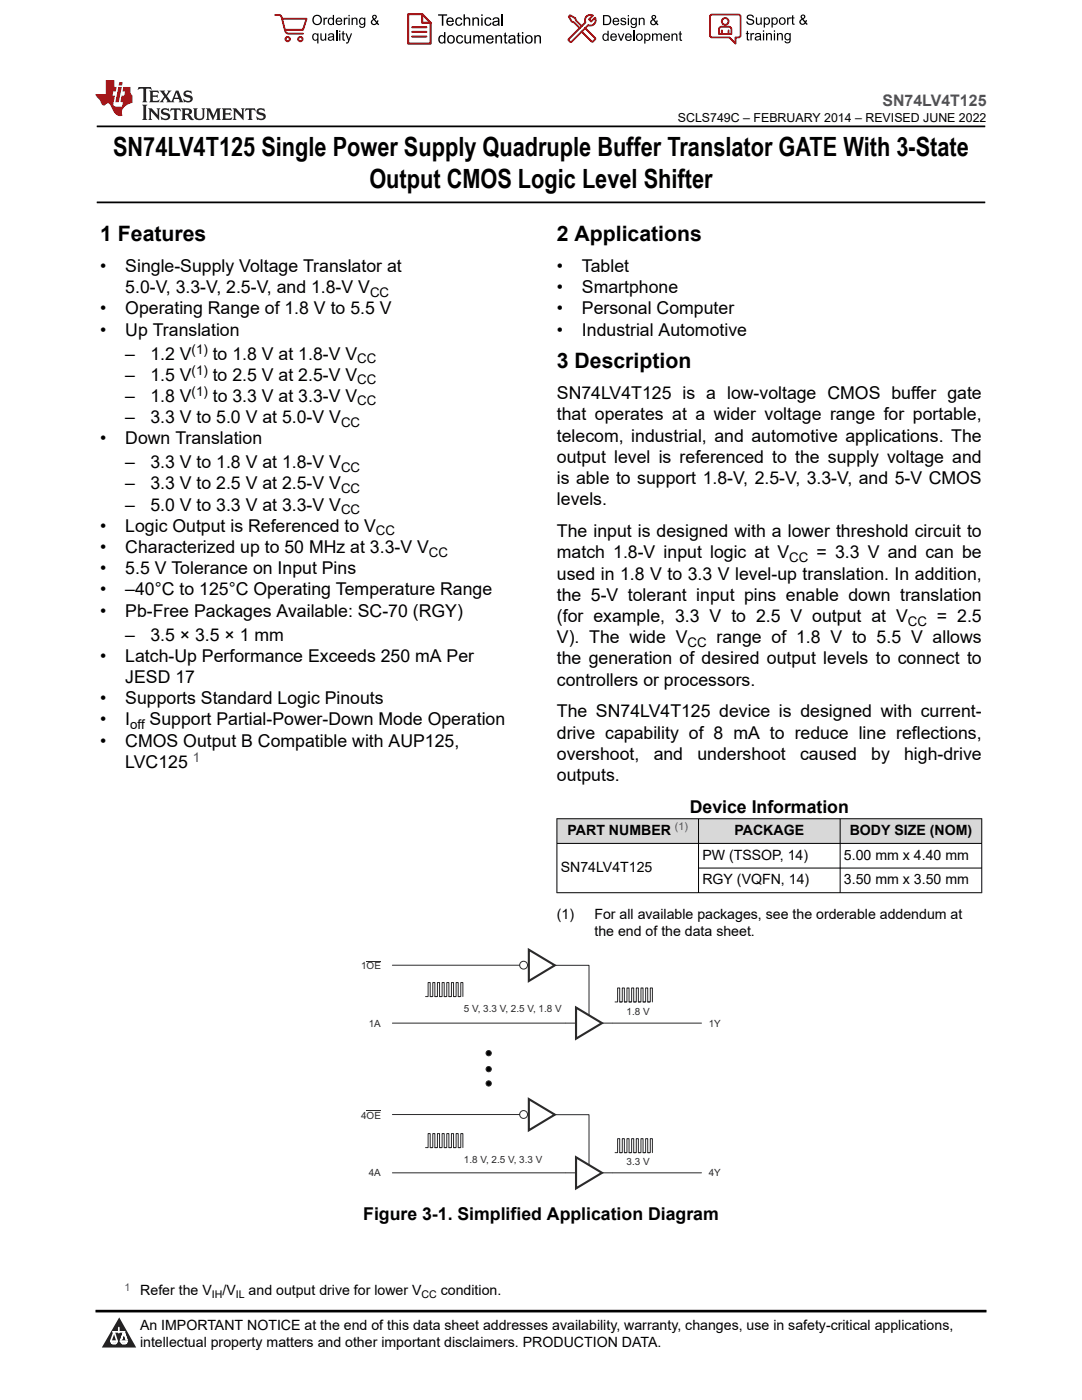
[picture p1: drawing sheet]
<svg xmlns="http://www.w3.org/2000/svg" width="216mm" height="279mm" viewBox="0 0 216 279" stroke-linecap="round" stroke-linejoin="round" font-family="sans-serif">
<defs><g id="words">
<g font-size="5.3">
<text x="22.6" y="31.2">SN74LV4T125 Single Power Supply Quadruple Buffer Translator GATE With 3-State</text>
<text x="73.7" y="37.5">Output CMOS Logic Level Shifter</text>
</g>
<g font-size="4.2">
<text x="20" y="48.1">1 Features</text>
<text x="111.1" y="48.1">2 Applications</text>
<text x="111.1" y="73.5">3 Description</text>
</g>
<g font-size="3.5">
<text x="20" y="54.3">•</text>
<text x="25" y="54.3">Single-Supply Voltage Translator at</text>
<text x="25" y="58.5">5.0-V, 3.3-V, 2.5-V, and 1.8-V V</text>
<text x="111.1" y="54.3">•</text>
<text x="111.1" y="58.5">•</text>
<text x="116.1" y="54.3">Tablet</text>
<text x="116.1" y="58.5">Smartphone</text>
<text x="20" y="62.8">•</text>
<text x="25" y="62.8">Operating Range of 1.8 V to 5.5 V</text>
<text x="111.1" y="62.8">•</text>
<text x="116.1" y="62.8">Personal Computer</text>
<text x="20" y="67">•</text>
<text x="25" y="67">Up Translation</text>
<text x="25" y="71.7">–</text>
<text x="30" y="71.7">1.2 V</text>
<text x="42.5" y="71.7">to 1.8 V at 1.8-V V</text>
<text x="111.1" y="67">•</text>
<text x="116.1" y="67">Industrial Automotive</text>
<text x="25" y="76">–</text>
<text x="30" y="76">1.5 V</text>
<text x="42.5" y="76">to 2.5 V at 2.5-V V</text>
<text x="25" y="80.2">–</text>
<text x="30" y="80.2">1.8 V</text>
<text x="42.5" y="80.2">to 3.3 V at 3.3-V V</text>
<text x="111.1" y="79.7">SN74LV4T125 is a low-voltage CMOS buffer gate</text>
<text x="111.1" y="83.9">that operates at a wider voltage range for portable,</text>
<text x="20" y="88.7">•</text>
<text x="25" y="88.7">Down Translation</text>
<text x="25" y="84.4">–</text>
<text x="30" y="84.4">3.3 V to 5.0 V at 5.0-V V</text>
<text x="111.1" y="88.2">telecom, industrial, and automotive applications. The</text>
<text x="25" y="93.4">–</text>
<text x="30" y="93.4">3.3 V to 1.8 V at 1.8-V V</text>
<text x="111.1" y="92.4">output level is referenced to the supply voltage and</text>
<text x="25" y="97.7">–</text>
<text x="25" y="101.9">–</text>
<text x="30" y="101.9">5.0 V to 3.3 V at 3.3-V V</text>
<text x="30" y="97.7">3.3 V to 2.5 V at 2.5-V V</text>
<text x="111.1" y="96.6">is able to support 1.8-V, 2.5-V, 3.3-V, and 5-V CMOS</text>
<text x="111.1" y="100.9">levels.</text>
<text x="20" y="106.1">•</text>
<text x="25" y="106.1">Logic Output is Referenced to V</text>
<text x="111.1" y="107.2">The input is designed with a lower threshold circuit to</text>
<text x="20" y="110.4">•</text>
<text x="25" y="110.4">Characterized up to 50 MHz at 3.3-V V</text>
<text x="111.1" y="111.4">match 1.8-V input logic at V</text>
<text x="162.9" y="111.4">= 3.3 V and can be</text>
<text x="20" y="114.6">•</text>
<text x="20" y="118.8">•</text>
<text x="25" y="114.6">5.5 V Tolerance on Input Pins</text>
<text x="25" y="118.8">–40°C to 125°C Operating Temperature Range</text>
<text x="111.1" y="115.7">used in 1.8 V to 3.3 V level-up translation. In addition,</text>
<text x="111.1" y="119.9">the 5-V tolerant input pins enable down translation</text>
<text x="20" y="123.1">•</text>
<text x="25" y="123.1">Pb-Free Packages Available: SC-70 (RGY)</text>
<text x="111.1" y="124.1">(for example, 3.3 V to 2.5 V output at V</text>
<text x="187" y="124.1">= 2.5</text>
<text x="25" y="127.8">–</text>
<text x="30" y="127.8">3.5 × 3.5 × 1 mm</text>
<text x="111.1" y="128.4">V). The wide V</text>
<text x="143" y="128.4">range of 1.8 V to 5.5 V allows</text>
<text x="20" y="132.1">•</text>
<text x="25" y="132.1">Latch-Up Performance Exceeds 250 mA Per</text>
<text x="25" y="136.3">JESD 17</text>
<text x="111.1" y="136.8">controllers or processors.</text>
<text x="111.1" y="132.6">the generation of desired output levels to connect to</text>
<text x="20" y="140.5">•</text>
<text x="25" y="140.5">Supports Standard Logic Pinouts</text>
<text x="111.1" y="143.2">The SN74LV4T125 device is designed with current-</text>
<text x="20" y="149">•</text>
<text x="20" y="144.8">•</text>
<text x="25" y="144.8">I</text>
<text x="25" y="149">CMOS Output B Compatible with AUP125,</text>
<text x="29.9" y="144.8">Support Partial-Power-Down Mode Operation</text>
<text x="111.1" y="147.4">drive capability of 8 mA to reduce line reflections,</text>
<text x="25" y="153.2">LVC125</text>
<text x="111.1" y="151.7">overshoot,</text>
<text x="111.1" y="155.9">outputs.</text>
<text x="130.4" y="151.7">and</text>
<text x="139.2" y="151.7">undershoot</text>
<text x="159.6" y="151.7">caused</text>
<text x="173.8" y="151.7">by</text>
<text x="180.4" y="151.7">high-drive</text>
<text x="137.6" y="162.2">Device Information</text>
<text x="72.5" y="243.5">Figure 3-1. Simplified Application Diagram</text>
</g>
<text font-size="3.2" fill="#00f" x="176.1" y="21.1">SN74LV4T125</text>
<g font-size="2.8">
<text x="113.2" y="166.7">PART NUMBER</text>
<text x="146.6" y="166.7">PACKAGE</text>
<text x="169.5" y="166.7">BODY SIZE (NOM)</text>
<text x="140.2" y="171.6">PW (TSSOP, 14)</text>
<text x="168.4" y="171.6">5.00 mm x 4.40 mm</text>
<text x="111.9" y="174.1">SN74LV4T125</text>
<text x="140.2" y="176.5">RGY (VQFN, 14)</text>
<text x="168.4" y="176.5">3.50 mm x 3.50 mm</text>
<text x="111.1" y="183.3">(1)</text>
<text x="118.6" y="183.3">For all available packages, see the orderable addendum at</text>
<text x="118.6" y="186.7">the end of the data sheet.</text>
<text x="28" y="258.5">Refer the V</text>
<text x="44.4" y="258.5">/V</text>
<text x="49.6" y="258.5">and output drive for lower V</text>
<text x="88" y="258.5">condition.</text>
<text x="27.9" y="265.5">An IMPORTANT NOTICE at the end of this data sheet addresses availability, warranty, changes, use in safety-critical applications,</text>
<text x="27.9" y="268.9">intellectual property matters and other important disclaimers. PRODUCTION DATA.</text>
</g>
<g font-size="2.6">
<text x="73.8" y="59.2">CC</text>
<text x="38.2" y="70.6">(1)</text>
<text x="38.2" y="74.8">(1)</text>
<text x="71.3" y="76.7">CC</text>
<text x="71.3" y="72.5">CC</text>
<text x="38.2" y="79">(1)</text>
<text x="71.3" y="80.9">CC</text>
<text x="68" y="85.2">CC</text>
<text x="68" y="94.1">CC</text>
<text x="68" y="98.4">CC</text>
<text x="68" y="102.6">CC</text>
<text x="75" y="106.8">CC</text>
<text x="85.6" y="111.1">CC</text>
<text x="157.5" y="112.1">CC</text>
<text x="181.1" y="124.8">CC</text>
<text x="137.2" y="129.1">CC</text>
<text x="26" y="145.5">off</text>
</g>
<text font-size="2.6" fill="#00f" x="38.5" y="152.1">1</text>
<text font-size="2.5" x="135.3" y="24.3">SCLS749C – FEBRUARY 2014 – REVISED JUNE 2022</text>
<g font-size="2.1" fill="#00f">
<text x="134.7" y="165.7">(1)</text>
<text x="24.8" y="257.6">1</text>
</g>
<g font-size="2.1">
<text x="42.3" y="259.1">IH</text>
<text x="47.1" y="259.1">IL</text>
<text x="84.1" y="259.1">CC</text>
</g>
<g font-size="2" fill="#2b292a">
<text x="72.1" y="193.5">1OE</text>
<text x="92.5" y="202">5 V, 3.3 V, 2.5 V, 1.8 V</text>
<text x="125" y="202.5">1.8 V</text>
<text x="73.6" y="204.9">1A</text>
<text x="141.4" y="204.9">1Y</text>
<text x="72.1" y="223.3">4OE</text>
<text x="92.6" y="232.2">1.8 V, 2.5 V, 3.3 V</text>
<text x="125" y="232.6">3.3 V</text>
<text x="73.6" y="234.8">4A</text>
<text x="141.4" y="234.8">4Y</text>
</g>
</g></defs>
<path d="M19.3 25.2h177.3M19.3 40.4h177.3" fill="none" stroke="#000" stroke-width=".35"/>
<g fill="#d8d8d8">
<path d="M111.1 163.4h84.8v4.9h-84.8z" fill-rule="evenodd"/>
<path d="M111.2 163.5h28.1v4.8h-28.1z" fill-rule="evenodd"/>
<path d="M139.4 163.5h28.2v4.8h-28.2z" fill-rule="evenodd"/>
<path d="M167.7 163.5h28.1v4.8h-28.1z" fill-rule="evenodd"/>
</g>
<path d="M111.1 163.4h84.9M111.1 168.3h84.9M111.1 178.2h84.9M111.1 163.3v14.9M139.4 163.3v14.9M139.4 173.2h56.6M167.6 163.3v14.9M195.9 163.3v14.9" fill="none" stroke="#000" stroke-width=".2"/>
<g fill="none" stroke="#2b292a" stroke-width=".2">
<path d="M73.2 191.8h2.8M78.3 192.6h25.4M84.9 198.9h.5v-2.8h.4v2.8h.4M85.8 198.9h.6v-2.8h.4v2.8h.4M86.8 198.9h.5v-2.8h.4v2.8h.4M87.7 198.9h.5v-2.8h.4v2.8h.4M88.6 198.9h.5v-2.8h.5v2.8h.4M89.6 198.9h.5v-2.8h.4v2.8h.4M90.5 198.9h.5v-2.8h.4v2.8h.4M91.4 198.9h.5v-2.8h.5v2.8M110.7 192.6h6.8v10M122.7 200h.5v-2.8h.5v2.8h.4"/>
<path d="M123.7 200h.5v-2.8h.4v2.8h.4M124.6 200h.5v-2.8h.4v2.8h.4M125.5 200h.5v-2.8h.5v2.8h.3M126.5 200h.5v-2.8h.4v2.8h.4M127.4 200h.5v-2.8h.4v2.8h.4M128.3 200h.5v-2.8h.4v2.8h.4M129.2 200h.6v-2.8h.4v2.8M78.3 204.2h36.6M120.1 204.2h19.9M73.2 221.6h2.8M78.3 234.1h36.6M78.3 222.4h25.4"/>
<path d="M84.9 229h.5v-2.8h.4v2.8h.4M85.8 229h.6v-2.8h.4v2.8h.4M86.8 229h.5v-2.8h.4v2.8h.4M87.7 229h.5v-2.8h.4v2.8h.4M88.6 229h.5v-2.8h.5v2.8h.4M89.6 229h.5v-2.8h.4v2.8h.4M90.5 229h.5v-2.8h.4v2.8h.4M91.4 229h.5v-2.8h.5v2.8M110.7 222.5h6.8v9.9M120.1 234.1h19.9M122.7 230h.5v-2.8h.5v2.8h.4M123.7 230h.5v-2.8h.4v2.8h.4"/>
<path d="M124.6 230h.5v-2.8h.4v2.8h.4M125.5 230h.5v-2.8h.5v2.8h.3M126.5 230h.5v-2.8h.4v2.8h.4M127.4 230h.5v-2.8h.4v2.8h.4M128.3 230h.5v-2.8h.4v2.8h.4M129.2 230h.6v-2.8h.4v2.8"/>
<circle cx="104.5" cy="192.6" r=".78"/>
<circle cx="97.5" cy="213.4" r=".53"/>
<circle cx="97.5" cy="216.2" r=".53"/>
<circle cx="97.5" cy="210.2" r=".53"/>
<circle cx="104.5" cy="222.4" r=".78"/>
</g>
<path d="M105.5 189.5l5.2 3.1-5.2 3.2zM105.5 219.3l5.2 3.1-5.2 3.2zM114.9 201.1l5.2 3.1-5.2 3.1zM114.9 231l5.2 3.1-5.2 3.1z" fill="none" stroke="#2b292a" stroke-width=".42"/>
<g fill="#000">
<circle cx="97.5" cy="213.4" r=".53"/>
<circle cx="97.5" cy="216.2" r=".53"/>
<circle cx="97.5" cy="210.2" r=".53"/>
</g>
<path d="M0 0h215.9v23.8h-215.9z" fill-rule="evenodd" fill="#fff"/>
<path d="M27.7 17.4l-.2 .6 .5-.3h.6v.1v2.2l-.2 .4h1l-.2-.4v-2.2v-.1h.5l.5 .3-.1-.6zM29.8 18.1l.2 .4v1.5l-.2 .4h1.9l.1-.6a1.08 1.08 0 0 1-1.3 .2v-.7h.6l.4 .2v-.6l-.4 .2h-.6v-.6l.2-.1a1 1 0 0 1 1 .2l-.1-.5zM31.8 18.1l1 1.1-1 1.2h.9l-.2-.2 .4-.7 .5 .7-.2 .2h1.6l-.2-.2 .1-.4h1l.1 .4-.1 .2h.9l-.2-.3-.8-2h-.5l-1 2.2-.8-1.1 .9-1.1h-.8l.2 .2-.5 .7-.3-.7 .1-.2zM35.2 18.5l.4 1h-.8zM36.8 18.2a.65 .65 0 0 0-.2 .7 .65 .65 0 0 0 .6 .5l.7 .2 .1 .2a.79 .79 0 0 1-.7 .4 .79 .79 0 0 1-.7-.5l.1 .7 .2-.1a.93 .93 0 0 0 1.1 .1 .93 .93 0 0 0 .4-1 1.46 1.46 0 0 0-1.2-.6l-.1-.3a1.09 1.09 0 0 1 1.2 .2l-.2-.6-.1 .1-.6-.2zM28.4 20.9l.2 .4v2.3l-.2 .3h1l-.2-.3v-2.3l.2-.4zM29.6 21.6l.2 .4v1.6l-.2 .3h.8l-.3-.3v-1.4l1.7 1.8v-2l.2-.4h-.8l.2 .2 .1 1.1-1.2-1.3zM32.3 21.8a.65 .65 0 0 0-.2 .7 .65 .65 0 0 0 .7 .4l.6 .2 .1 .2a.79 .79 0 0 1-.7 .4 .79 .79 0 0 1-.7-.5l.1 .7 .2-.1a.93 .93 0 0 0 1.1 .1 .93 .93 0 0 0 .4-.9 1.46 1.46 0 0 0-1.2-.6l-.1-.4a1.09 1.09 0 0 1 1.2 .2l-.2-.6-.1 .1-.6-.1zM34.1 21.6l-.1 .7a.63 .63 0 0 1 .7-.4l.1 1.7-.3 .3h1l-.2-.3v-1.7a.66 .66 0 0 1 .8 .4l-.1-.7zM36.2 21.6l.2 .4v1.6l-.2 .3h.9l-.2-.2v-.7h.5l.1 .2a.79 .79 0 0 0 1.2 .6l-1-.9a.61 .61 0 0 0 .6-.6 .61 .61 0 0 0-.5-.6zM36.9 21.9h.2a.47 .47 0 0 1 .5 .1 .47 .47 0 0 1 .1 .5l-.2 .2h-.6zM38.5 21.6l.2 .2a2.27 2.27 0 0 0 .4 2 1.04 1.04 0 0 0 1.7-.7v-1.3l.2-.2h-.8l.2 .4v1.1a.6 .6 0 0 1-.6 .6 .6 .6 0 0 1-.6-.6v-1.1l.3-.4zM41.1 21.6l.2 .4v1.6l-.2 .3h.7l-.2-.3v-1.5l.9 1.9 .8-1.9v1.5l-.2 .3h1l-.3-.3v-1.6l.3-.4h-.8l-.7 1.5-.7-1.5zM44.3 21.6l.2 .4v1.6l-.2 .3h1.9l.1-.5a1.09 1.09 0 0 1-1.3 .1v-.6h.6l.4 .1v-.6l-.4 .2h-.6v-.6l.2-.1a1.01 1.01 0 0 1 1 .3l-.1-.6zM46.4 21.6l.3 .4v1.6l-.3 .3h.8l-.2-.3v-1.4l1.6 1.8v-2l.2-.4h-.7l.2 .2v1.1l-1.2-1.3zM49 21.6l-.1 .7a.63 .63 0 0 1 .8-.4v1.7l-.3 .3h1l-.2-.3v-1.7a.66 .66 0 0 1 .8 .4l-.1-.7zM51.4 21.8a.65 .65 0 0 0-.2 .7 .65 .65 0 0 0 .6 .4l.6 .2 .2 .2a.79 .79 0 0 1-.8 .4 .79 .79 0 0 1-.6-.5l.1 .7 .2-.1a.93 .93 0 0 0 1 .1 .93 .93 0 0 0 .5-.9 1.46 1.46 0 0 0-1.3-.6l-.1-.4a1.09 1.09 0 0 1 1.3 .2l-.2-.6-.2 .1-.5-.1z" fill="#231f20"/>
<path d="M21.1 16v2.8h-2.1l.1 .3 .9 1a.95 .95 0 0 0 .9 .9 .59 .59 0 0 1 .6-.4 .59 .59 0 0 1 .5 .4l.4 .8a1.59 1.59 0 0 0 2.1 1.3 1.61 1.61 0 0 1 1-2.2l1-.4-.1-1.5a1.59 1.59 0 0 1-.4-1.6h-1.4l-.2 .9h.5l-.1 .8h-.5l-.2 1v.2l.4 .1-.2 .9h-.6a.73 .73 0 0 1-1.1-.7l.3-1.5h-.5l.2-.8h.5l.2-.9h-.5v-1.4zM23.6 17.4l-.6 3h.7l.6-3zM23.8 16.4l-.1 .7h.7l.1-.7z" fill="#ed1c24"/>
<g fill="#000">
<path d="M62.3 4a1 1 0 0 1 2 0 1 1 0 0 1-2 0zM62.8 3.4a.78 .78 0 0 0-.1 1.1 .78 .78 0 0 0 1.1 .1 .78 .78 0 0 0 .1-1.1 .78 .78 0 0 0-1.1-.1z" fill-rule="evenodd"/>
<path d="M62.5 6.8l.4-.2 .4 .3v-.2h.2v2h-.2v-.7a.68 .68 0 0 1-.9-.1 .68 .68 0 0 1 0-.9zM62.6 7a.51 .51 0 0 0-.1 .6 .51 .51 0 0 0 .7 .2 .51 .51 0 0 0 .1-.7 .51 .51 0 0 0-.7-.1z" fill-rule="evenodd"/>
<path d="M64.5 3.5h.3v.3l.1-.3h.3l.1 .1-.1 .2a.32 .32 0 0 0-.3 0 .32 .32 0 0 0-.1 .4v.8h-.3z" fill-rule="evenodd"/>
<path d="M63.9 6.7h.3v.8a.36 .36 0 0 0 .3 .4 .36 .36 0 0 0 .4-.5v-.7h.2v1.4h-.2v-.2a.51 .51 0 0 1-.6 .2 .51 .51 0 0 1-.4-.5z" fill-rule="evenodd"/>
<path d="M65.6 3.7l.4-.2 .4 .2v-.7h.3v2h-.3v-.2a.7 .7 0 0 1-1-.1 .7 .7 0 0 1 .2-1zM65.8 3.8a.51 .51 0 0 0-.1 .7 .51 .51 0 0 0 .6 .2 .51 .51 0 0 0 .1-.7 .51 .51 0 0 0-.6-.2z" fill-rule="evenodd"/>
<path d="M65.6 6.8a.66 .66 0 0 1 .8-.1 .66 .66 0 0 1 .3 .8v.6h-.2l-.1-.2a.52 .52 0 0 1-.7 .2 .52 .52 0 0 1-.2-.6l.3-.2a.42 .42 0 0 0 .6-.3l-.3-.2-.3 .1-.1 .2h-.3zM65.7 7.6a.35 .35 0 0 0 .3 .4 .35 .35 0 0 0 .4-.4v-.2z" fill-rule="evenodd"/>
<path d="M67.7 6.1h.2v.3h-.2zM67.7 6.7h.2v1.4h-.2z" fill-rule="evenodd"/>
<path d="M67.1 3.7a.68 .68 0 0 1 .9-.1 .68 .68 0 0 1 .3 .7h-1.1a.42 .42 0 0 0 .3 .5 .42 .42 0 0 0 .5-.3h.3a.73 .73 0 0 1-1.1 .4 .73 .73 0 0 1-.1-1.2zM67.4 3.8l-.2 .3h.8l-.2-.4z" fill-rule="evenodd"/>
<path d="M68.6 3.5h.2v.3l.2-.3h.3l.1 .1-.1 .2a.32 .32 0 0 0-.4 0 .32 .32 0 0 0-.1 .4v.8h-.2z" fill-rule="evenodd"/>
<path d="M68.3 6.3l.3-.1v.5h.2v.1h-.2v.9l.3 .4a.36 .36 0 0 1-.4 0 .36 .36 0 0 1-.2-.4v-.9h-.1v-.1h.1z" fill-rule="evenodd"/>
<path d="M68.9 6.7h.3l.4 1.1 .4-1.1h.3l-.6 1.4a.51 .51 0 0 1-.6 .6l-.1-.3h.3l.2-.3z" fill-rule="evenodd"/>
<path d="M69.5 3h.3v.3h-.3zM69.5 3.5h.3v1.5h-.3z" fill-rule="evenodd"/>
<path d="M70.2 3.5h.2v.2a.52 .52 0 0 1 .6-.2 .52 .52 0 0 1 .3 .6v.9h-.2v-.9a.34 .34 0 0 0-.3-.4 .34 .34 0 0 0-.4 .3v1h-.2z" fill-rule="evenodd"/>
<path d="M71.8 3.7l.4-.2 .5 .2v-.2h.2v1.3a.64 .64 0 0 1-.5 .8 .64 .64 0 0 1-.7-.5h.2a.41 .41 0 0 0 .5 .2 .41 .41 0 0 0 .2-.5 .69 .69 0 0 1-.9-.1 .69 .69 0 0 1 .1-1zM72 3.8a.5 .5 0 0 0-.1 .7 .5 .5 0 0 0 .7 .1 .5 .5 0 0 0 .1-.6 .5 .5 0 0 0-.7-.2z" fill-rule="evenodd"/>
<path d="M74.4 3.1a.47 .47 0 0 1 .7 .1 .47 .47 0 0 1-.3 .7l.4 .4 .1-.3 .2 .1-.1 .4 .3 .3-.2 .2-.3-.3a.63 .63 0 0 1-1 .1 .63 .63 0 0 1 .3-1l-.3-.4zM74.5 3.4a.27 .27 0 0 0 .5 0 .27 .27 0 0 0-.5 0zM74.4 4.1a.4 .4 0 0 0 0 .6 .4 .4 0 0 0 .6-.1l-.4-.6z" fill-rule="evenodd"/>
<path d="M87.4 2.9h1.8v.2h-.7v2h-.3v-2h-.8z" fill-rule="evenodd"/>
<path d="M87.6 7.2l.5-.2 .5 .2v-.8h.3v2.3h-.3v-.2a.76 .76 0 0 1-1-.1 .76 .76 0 0 1-.1-1zM87.9 7.4a.58 .58 0 0 0-.2 .7 .58 .58 0 0 0 .8 .2 .58 .58 0 0 0 .1-.7 .58 .58 0 0 0-.7-.2z" fill-rule="evenodd"/>
<path d="M89.5 7.2a.81 .81 0 0 1 1.1 .1 .81 .81 0 0 1-.2 1.2 .81 .81 0 0 1-1.1-.2l-.1-.7zM89.6 7.4a.57 .57 0 0 0 0 .8 .57 .57 0 0 0 .8 0 .57 .57 0 0 0 0-.7 .57 .57 0 0 0-.8-.1z" fill-rule="evenodd"/>
<path d="M89.3 3.7a.77 .77 0 0 1 .9-.2 .77 .77 0 0 1 .4 .9h-1.3a.48 .48 0 0 0 .4 .5 .48 .48 0 0 0 .6-.3h.3a.83 .83 0 0 1-1.3 .4 .83 .83 0 0 1 0-1.3zM89.5 3.8l-.2 .4h1l-.3-.5z" fill-rule="evenodd"/>
<path d="M91 3.7a.7 .7 0 0 1 1.2 .3h-.2a.45 .45 0 0 0-.6-.3 .45 .45 0 0 0-.3 .6 .45 .45 0 0 0 .3 .6 .45 .45 0 0 0 .6-.4l.3 .1a.76 .76 0 0 1-1.1 .5 .76 .76 0 0 1-.3-1.1z" fill-rule="evenodd"/>
<path d="M91.2 7.2a.7 .7 0 0 1 1.2 .3l-.3 .1a.45 .45 0 0 0-.5-.4 .45 .45 0 0 0-.3 .7 .45 .45 0 0 0 .3 .6 .45 .45 0 0 0 .6-.4h.2a.76 .76 0 0 1-1 .5 .76 .76 0 0 1-.4-1.1z" fill-rule="evenodd"/>
<path d="M92.5 2.9h.3v.8a.59 .59 0 0 1 .7-.2 .59 .59 0 0 1 .3 .6v1h-.2v-1a.4 .4 0 0 0-.5-.4 .4 .4 0 0 0-.3 .5v.9h-.3z" fill-rule="evenodd"/>
<path d="M92.7 7h.2v.9a.41 .41 0 0 0 .5 .6 .41 .41 0 0 0 .3-.6v-.9h.3v1.7h-.3v-.3a.58 .58 0 0 1-.7 .3 .58 .58 0 0 1-.3-.7z" fill-rule="evenodd"/>
<path d="M94.3 3.5h.2v.2a.59 .59 0 0 1 .7-.2 .59 .59 0 0 1 .4 .6v1h-.3v-1a.41 .41 0 0 0-.4-.4 .41 .41 0 0 0-.4 .5v.9h-.2z" fill-rule="evenodd"/>
<path d="M94.4 7h.3v.3a.56 .56 0 0 1 1 0 .54 .54 0 0 1 .6-.3 .54 .54 0 0 1 .4 .5v1.2h-.3v-1.1a.34 .34 0 0 0-.3-.4 .34 .34 0 0 0-.4 .3v1.2h-.3v-1.1a.38 .38 0 0 0-.5-.3 .38 .38 0 0 0-.2 .5v.9h-.3z" fill-rule="evenodd"/>
<path d="M96 2.9h.3v.3h-.3zM96 3.5h.3v1.6h-.3z" fill-rule="evenodd"/>
<path d="M96.8 3.7a.7 .7 0 0 1 1.3 .3h-.3a.45 .45 0 0 0-.6-.3 .45 .45 0 0 0-.3 .6 .45 .45 0 0 0 .3 .6 .45 .45 0 0 0 .6-.4l.3 .1a.76 .76 0 0 1-1.1 .5 .76 .76 0 0 1-.3-1.1z" fill-rule="evenodd"/>
<path d="M97.2 7.2a.77 .77 0 0 1 .9-.1 .77 .77 0 0 1 .4 .8h-1.2a.48 .48 0 0 0 .3 .6 .48 .48 0 0 0 .6-.4l.3 .1a.83 .83 0 0 1-1.3 .3 .83 .83 0 0 1 0-1.3zM97.4 7.4l-.1 .3h.9l-.2-.4z" fill-rule="evenodd"/>
<path d="M98.8 7h.3v.3a.59 .59 0 0 1 .7-.3 .59 .59 0 0 1 .4 .7v1h-.3v-1a.41 .41 0 0 0-.5-.5 .41 .41 0 0 0-.3 .6v.9h-.3z" fill-rule="evenodd"/>
<path d="M98.4 3.7a.74 .74 0 0 1 1-.2 .74 .74 0 0 1 .3 .9v.7h-.3v-.2a.59 .59 0 0 1-.8 .3 .59 .59 0 0 1-.3-.8l1.1-.3a.42 .42 0 0 0-.4-.4 .42 .42 0 0 0-.5 .3h-.2zM98.6 4.5a.36 .36 0 0 0 .2 .5 .36 .36 0 0 0 .5-.2l.1-.5z" fill-rule="evenodd"/>
<path d="M100.7 6.6l.2-.1v.5h.3v.2h-.3v1l.1 .2h.2l.1 .3a.41 .41 0 0 1-.5-.1 .41 .41 0 0 1-.1-.4v-1h-.2v-.2h.2z" fill-rule="evenodd"/>
<path d="M101.6 7.2a.74 .74 0 0 1 .9-.2 .74 .74 0 0 1 .3 1l.1 .7h-.3v-.2a.59 .59 0 0 1-.8 .2 .59 .59 0 0 1-.3-.8l1-.3a.42 .42 0 0 0-.3-.4 .42 .42 0 0 0-.5 .3h-.3zM101.8 8.1a.36 .36 0 0 0 .1 .5 .36 .36 0 0 0 .5-.3l.2-.4z" fill-rule="evenodd"/>
<path d="M103.3 6.6l.3-.1v.5h.3v.2h-.3v1l.1 .2h.2v.3a.41 .41 0 0 1-.5-.1 .41 .41 0 0 1-.1-.4v-1h-.2v-.2h.2z" fill-rule="evenodd"/>
<path d="M104.1 6.4h.3v.3h-.3zM104.1 7h.3v1.7h-.3z" fill-rule="evenodd"/>
<path d="M105 7.2a.81 .81 0 0 1 1.1 .1 .81 .81 0 0 1-.1 1.2 .81 .81 0 0 1-1.2-.2v-.7zM105.2 7.4a.57 .57 0 0 0-.1 .8 .57 .57 0 0 0 .8 0 .57 .57 0 0 0 0-.7 .57 .57 0 0 0-.7-.1z" fill-rule="evenodd"/>
<path d="M106.6 7h.3v.3a.59 .59 0 0 1 .7-.3 .59 .59 0 0 1 .4 .7v1h-.3v-1a.41 .41 0 0 0-.5-.5 .41 .41 0 0 0-.3 .6v.9h-.3z" fill-rule="evenodd"/>
<path d="M120.3 3h.7a1 1 0 0 1 1 1 1 1 0 0 1-1 1h-.7zM120.6 3.2v1.6h.4a.77 .77 0 0 0 .7-.8 .77 .77 0 0 0-.7-.8z" fill-rule="evenodd"/>
<path d="M120.4 6.9l.4-.2 .4 .2v-.8h.3v2h-.3v-.1a.7 .7 0 0 1-.9-.2 .7 .7 0 0 1 .1-.9zM120.6 7a.51 .51 0 0 0-.1 .7 .51 .51 0 0 0 .6 .1 .51 .51 0 0 0 .1-.6 .51 .51 0 0 0-.6-.2z" fill-rule="evenodd"/>
<path d="M122 6.9a.68 .68 0 0 1 .8-.2 .68 .68 0 0 1 .3 .8h-1.1a.42 .42 0 0 0 .3 .5 .42 .42 0 0 0 .5-.3h.3a.73 .73 0 0 1-1.1 .3 .73 .73 0 0 1 0-1.1zM122.2 7l-.2 .3h.8l-.2-.4z" fill-rule="evenodd"/>
<path d="M122.4 3.7a.68 .68 0 0 1 .8-.1 .68 .68 0 0 1 .4 .8h-1.1a.42 .42 0 0 0 .3 .4 .42 .42 0 0 0 .5-.3l.3 .1a.73 .73 0 0 1-1.2 .3 .73 .73 0 0 1 0-1.2zM122.6 3.8l-.1 .3h.8l-.2-.3z" fill-rule="evenodd"/>
<path d="M123.9 3.7l.1-.1a.62 .62 0 0 1 .9 .3l-.2 .1a.29 .29 0 0 0-.3-.3 .29 .29 0 0 0-.3 .3l.1 .1a.58 .58 0 0 1 .6 .1 .58 .58 0 0 1 .1 .6 .67 .67 0 0 1-1.1-.2l.2-.1a.33 .33 0 0 0 .4 .4 .33 .33 0 0 0 .3-.4 .71 .71 0 0 1-.9-.6z" fill-rule="evenodd"/>
<path d="M123.3 6.7h.2l.4 1.2 .4-1.2h.3l-.6 1.4h-.2z" fill-rule="evenodd"/>
<path d="M125.3 3h.2v.3h-.2zM125.3 3.6h.2v1.4h-.2z" fill-rule="evenodd"/>
<path d="M124.9 6.9a.68 .68 0 0 1 .8-.2 .68 .68 0 0 1 .4 .8h-1.1a.42 .42 0 0 0 .3 .5 .42 .42 0 0 0 .5-.3h.3a.73 .73 0 0 1-1.2 .3 .73 .73 0 0 1 0-1.1zM125.1 7l-.1 .3h.8l-.2-.4z" fill-rule="evenodd"/>
<path d="M126 3.7l.4-.2 .4 .2v-.1h.3v1.2a.64 .64 0 0 1-.5 .8 .64 .64 0 0 1-.8-.5l.3 .1a.41 .41 0 0 0 .5 .2 .41 .41 0 0 0 .2-.6 .69 .69 0 0 1-.9-.1 .69 .69 0 0 1 .1-1zM126.2 3.9a.5 .5 0 0 0-.1 .6 .5 .5 0 0 0 .6 .2 .5 .5 0 0 0 .2-.7 .5 .5 0 0 0-.7-.1z" fill-rule="evenodd"/>
<path d="M126.9 7.4a.73 .73 0 0 1 1.4 0 .73 .73 0 0 1-1.4 0zM127.3 7a.5 .5 0 0 0-.1 .7 .5 .5 0 0 0 .7 0 .5 .5 0 0 0 0-.6 .5 .5 0 0 0-.6-.1z" fill-rule="evenodd"/>
<path d="M127.5 3.6h.2v.2a.52 .52 0 0 1 .6-.3 .52 .52 0 0 1 .3 .6v.9h-.2v-.9a.34 .34 0 0 0-.3-.4 .34 .34 0 0 0-.4 .3v1h-.2z" fill-rule="evenodd"/>
<path d="M128.5 6.7h.3v.2a.67 .67 0 0 1 .9 0 .67 .67 0 0 1 0 .9 .55 .55 0 0 1-.9 .2v.7h-.3zM128.9 7a.5 .5 0 0 0-.1 .7 .5 .5 0 0 0 .6 .1 .5 .5 0 0 0 .2-.6 .5 .5 0 0 0-.7-.2z" fill-rule="evenodd"/>
<path d="M130.1 6.7h.2v.2a.49 .49 0 0 1 .9 0l.4-.2a.42 .42 0 0 1 .5 .4v1h-.3v-.9a.3 .3 0 0 0-.2-.3 .3 .3 0 0 0-.4 .2v1h-.2v-.9a.33 .33 0 0 0-.5-.3 .33 .33 0 0 0-.2 .5v.7h-.2z" fill-rule="evenodd"/>
<path d="M130.1 3.1a.47 .47 0 0 1 .8 .1 .47 .47 0 0 1-.3 .7l.3 .4 .1-.2h.3l-.2 .5 .3 .3-.2 .2-.3-.3a.63 .63 0 0 1-1 .1 .63 .63 0 0 1 .3-1l-.2-.5zM130.2 3.5a.27 .27 0 0 0 .5 0 .27 .27 0 0 0-.5 0zM130.2 4.1a.4 .4 0 0 0 0 .7 .4 .4 0 0 0 .6-.2l-.5-.6z" fill-rule="evenodd"/>
<path d="M132.5 6.9a.68 .68 0 0 1 .9-.2 .68 .68 0 0 1 .3 .8h-1.1a.42 .42 0 0 0 .3 .5 .42 .42 0 0 0 .5-.3h.3a.73 .73 0 0 1-1.1 .3 .73 .73 0 0 1-.1-1.1zM132.7 7l-.1 .3h.8l-.2-.4z" fill-rule="evenodd"/>
<path d="M134 6.7h.2v.2a.52 .52 0 0 1 .6-.2 .52 .52 0 0 1 .4 .6v.8h-.3v-.8a.34 .34 0 0 0-.2-.4 .34 .34 0 0 0-.4 .2l-.1 1h-.2z" fill-rule="evenodd"/>
<path d="M135.6 6.3l.2-.1v.5h.3v.2h-.3v.8l.3 .4a.36 .36 0 0 1-.4 0 .36 .36 0 0 1-.1-.4v-.8h-.2v-.2h.2z" fill-rule="evenodd"/>
<path d="M149.2 3a.8 .8 0 0 1 1.2 .5h-.2a.44 .44 0 0 0-.5-.4 .44 .44 0 0 0-.4 .5l.2 .1a.9 .9 0 0 1 1 .8 .84 .84 0 0 1-.9 .5 .84 .84 0 0 1-.7-.7h.3a.52 .52 0 0 0 .5 .5 .52 .52 0 0 0 .5-.6l-.2-.1a.85 .85 0 0 1-1-.8z" fill-rule="evenodd"/>
<path d="M149 6.3l.3-.2v.5h.2v.2h-.2v.9l.2 .4a.36 .36 0 0 1-.4-.1 .36 .36 0 0 1-.1-.4v-.8h-.2v-.2h.2z" fill-rule="evenodd"/>
<path d="M149.7 6.6h.3v.2l.1-.2h.3l.1 .1-.1 .2a.32 .32 0 0 0-.3 0 .32 .32 0 0 0-.1 .4v.8h-.3z" fill-rule="evenodd"/>
<path d="M150.7 6.8a.66 .66 0 0 1 .9-.2 .66 .66 0 0 1 .3 .9v.6h-.2l-.1-.2a.52 .52 0 0 1-.7 .2 .52 .52 0 0 1-.2-.7l.2-.1a.42 .42 0 0 0 .7-.3l-.3-.2h-.3l-.1 .3-.3-.1zM150.9 7.5a.35 .35 0 0 0 .3 .5 .35 .35 0 0 0 .4-.4v-.3z" fill-rule="evenodd"/>
<path d="M150.8 3.5h.3v.8a.36 .36 0 0 0 .3 .5 .36 .36 0 0 0 .4-.5v-.8h.2v1.4h-.2v-.2a.51 .51 0 0 1-.6 .3 .51 .51 0 0 1-.4-.6z" fill-rule="evenodd"/>
<path d="M152.2 6.1h.3v.2h-.3zM152.2 6.6h.3v1.5h-.3z" fill-rule="evenodd"/>
<path d="M152.4 3.5h.2v.2a.67 .67 0 0 1 .9 0 .67 .67 0 0 1 .1 .9 .55 .55 0 0 1-1 .2v.7h-.2zM152.7 3.8a.5 .5 0 0 0-.1 .7 .5 .5 0 0 0 .7 .1 .5 .5 0 0 0 .1-.6 .5 .5 0 0 0-.7-.2z" fill-rule="evenodd"/>
<path d="M152.9 6.6h.2v.2a.52 .52 0 0 1 .6-.2 .52 .52 0 0 1 .3 .6v.9h-.2v-.9a.34 .34 0 0 0-.3-.4 .34 .34 0 0 0-.4 .2v1.1h-.2z" fill-rule="evenodd"/>
<path d="M153.9 3.5h.3v.2a.67 .67 0 0 1 .9 0 .67 .67 0 0 1 0 .9 .55 .55 0 0 1-.9 .2v.7h-.3zM154.3 3.8a.5 .5 0 0 0-.1 .7 .5 .5 0 0 0 .6 .1 .5 .5 0 0 0 .2-.6 .5 .5 0 0 0-.7-.2z" fill-rule="evenodd"/>
<path d="M154.4 6.1h.3v.2h-.3zM154.4 6.6h.3v1.5h-.3z" fill-rule="evenodd"/>
<path d="M155 6.6h.3v.2a.52 .52 0 0 1 .6-.2 .52 .52 0 0 1 .3 .6v.9h-.2v-.9a.34 .34 0 0 0-.3-.4 .34 .34 0 0 0-.4 .2v1.1h-.3z" fill-rule="evenodd"/>
<path d="M155.4 4.2a.75 .75 0 0 1 1.5 0 .75 .75 0 0 1-1.5 0zM155.8 3.8a.5 .5 0 0 0-.1 .7 .5 .5 0 0 0 .8 0 .5 .5 0 0 0 0-.7 .5 .5 0 0 0-.7 0z" fill-rule="evenodd"/>
<path d="M156.7 6.8l.4-.2 .5 .2v-.2h.2v1.3a.64 .64 0 0 1-.5 .7 .64 .64 0 0 1-.8-.4h.3a.41 .41 0 0 0 .5 .2 .41 .41 0 0 0 .2-.5 .69 .69 0 0 1-.9-.1 .69 .69 0 0 1 .1-1zM156.9 6.9a.5 .5 0 0 0-.1 .7 .5 .5 0 0 0 .6 .1 .5 .5 0 0 0 .2-.7 .5 .5 0 0 0-.7-.1z" fill-rule="evenodd"/>
<path d="M157.1 3.5h.2v.2l.1-.2h.3h.2l-.1 .3a.32 .32 0 0 0-.4 0 .32 .32 0 0 0-.1 .4v.7h-.2z" fill-rule="evenodd"/>
<path d="M158 3.1l.3-.1v.5h.2v.2h-.2v.8l.3 .4a.36 .36 0 0 1-.4 0 .36 .36 0 0 1-.2-.4v-.8h-.1v-.2h.1z" fill-rule="evenodd"/>
<path d="M159.9 3a.47 .47 0 0 1 .7 .1 .47 .47 0 0 1-.3 .7l.4 .5 .1-.3h.2l-.1 .5 .3 .3-.2 .2-.3-.3a.63 .63 0 0 1-1 .1 .63 .63 0 0 1 .3-1l-.3-.5zM160 3.4a.27 .27 0 0 0 .5 0 .27 .27 0 0 0-.5 0zM159.9 4.1a.4 .4 0 0 0 0 .6 .4 .4 0 0 0 .6-.2l-.4-.6z" fill-rule="evenodd"/>
</g>
<path d="M67.2 6.1v2M126.5 6.1v2" fill="none" stroke="#000" stroke-width=".25"/>
<g fill="none" stroke="#de0000" stroke-width=".37">
<path d="M54.9 3h.9a1.19 1.19 0 0 1 .6 1.2l.6 2.1a.85 .85 0 0 0 1 .4h2.5M56.3 3.7h4.9l-.7 2.2h-3.6M116.1 5.2l-1.2-1.1-.1-.5-1-.6-.3 .3 .6 1 .5 .2 1.1 1.1M116.8 5.6l1.9 2v.3l-.4 .4h-.3l-1.9-2zM116.8 5.6l.6-.6a1.07 1.07 0 0 0 1.2-.2 1.07 1.07 0 0 0 .1-1.3l-.7 .8-.5-.4 .8-.8a1.07 1.07 0 0 0-1.2 .2 1.07 1.07 0 0 0-.3 1.2l-3.3 3.3v.3l.3 .3h.2l2.1-2.1M141.7 3.1l.4-.2h5.3l.3 .2 .1 3.9-.2 .4-.8 .1v1.2l-1.3-1.2h-3.4l-.4-.2zM143.5 5.6l.5-.3 1.7 .1 .2 .5v.9h-2.4zM144 6.1v.7M145.4 6.1v.7"/>
<circle cx="57.4" cy="7.8" r=".44"/>
<circle cx="59.9" cy="7.8" r=".44"/>
<circle cx="144.7" cy="4.3" r=".67"/>
</g>
<path d="M100.2 2.9v2.2" fill="none" stroke="#000" stroke-width=".28"/>
<path d="M81.4 2.8h2.8v1.7h1.7v4.2h-4.5zM82.3 6.4h2.8M82.3 5.4h2.8M82.3 7.3h2.8M84.2 2.8l1.7 1.7" fill="none" stroke="#de0000" stroke-width=".42"/>
<path d="M0 261.4h215.9v18h-215.9z" fill-rule="evenodd" fill="#fff"/>
<path d="M23.8 262.9l3.4 6h-6.9z" fill="#231f20"/>
<path d="M22.1 267.7h1.3l-.4 .5h-.3a.55 .55 0 0 1-.6-.5z" fill-rule="evenodd" fill="#fff"/>
<path d="M22.1 267.7h1.3l-.4 .5h-.3a.55 .55 0 0 1-.6-.5z" fill="none" stroke="#231f20" stroke-width=".34"/>
<path d="M22.1 267.7h1.3l-.4 .5h-.5zM22.6 265.8h.1M22.6 265.8h2.3zM23.7 265.9h.1M23.7 264.9v1zM24 267.7h.1" fill="none" stroke="#fff" stroke-width=".34"/>
<path d="M24.7 265.8l-.7 1.9z" fill="#fff"/>
<path d="M24.7 265.8l-.7 1.9z" fill="none" stroke="#fff" stroke-width=".34"/>
<path d="M24.7 265.8l.7 1.9z" fill="#fff"/>
<path d="M24.7 265.8l.7 1.9zM25.3 267.7h.1" fill="none" stroke="#fff" stroke-width=".34"/>
<path d="M22.8 265.8l-.7 1.9z" fill="#fff"/>
<path d="M22.8 265.8l-.7 1.9z" fill="none" stroke="#fff" stroke-width=".34"/>
<path d="M22.8 265.8l.6 1.9z" fill="#fff"/>
<path d="M22.8 265.8l.6 1.9z" fill="none" stroke="#fff" stroke-width=".34"/>
<path d="M24.1 267.7h1.3a.65 .65 0 0 1-.6 .5 .65 .65 0 0 1-.7-.5z" fill-rule="evenodd" fill="#fff"/>
<path d="M24.1 267.7h1.3a.65 .65 0 0 1-.6 .5 .65 .65 0 0 1-.7-.5z" fill="none" stroke="#231f20" stroke-width=".34"/>
<path d="M24 267.7h.1M24.1 267.7h1.3l-.4 .5h-.5z" fill="none" stroke="#fff" stroke-width=".34"/>
<path d="M19 261.7h177.8" fill="none" stroke="#000" stroke-width=".53"/>
<use href="#words"/>
</svg>
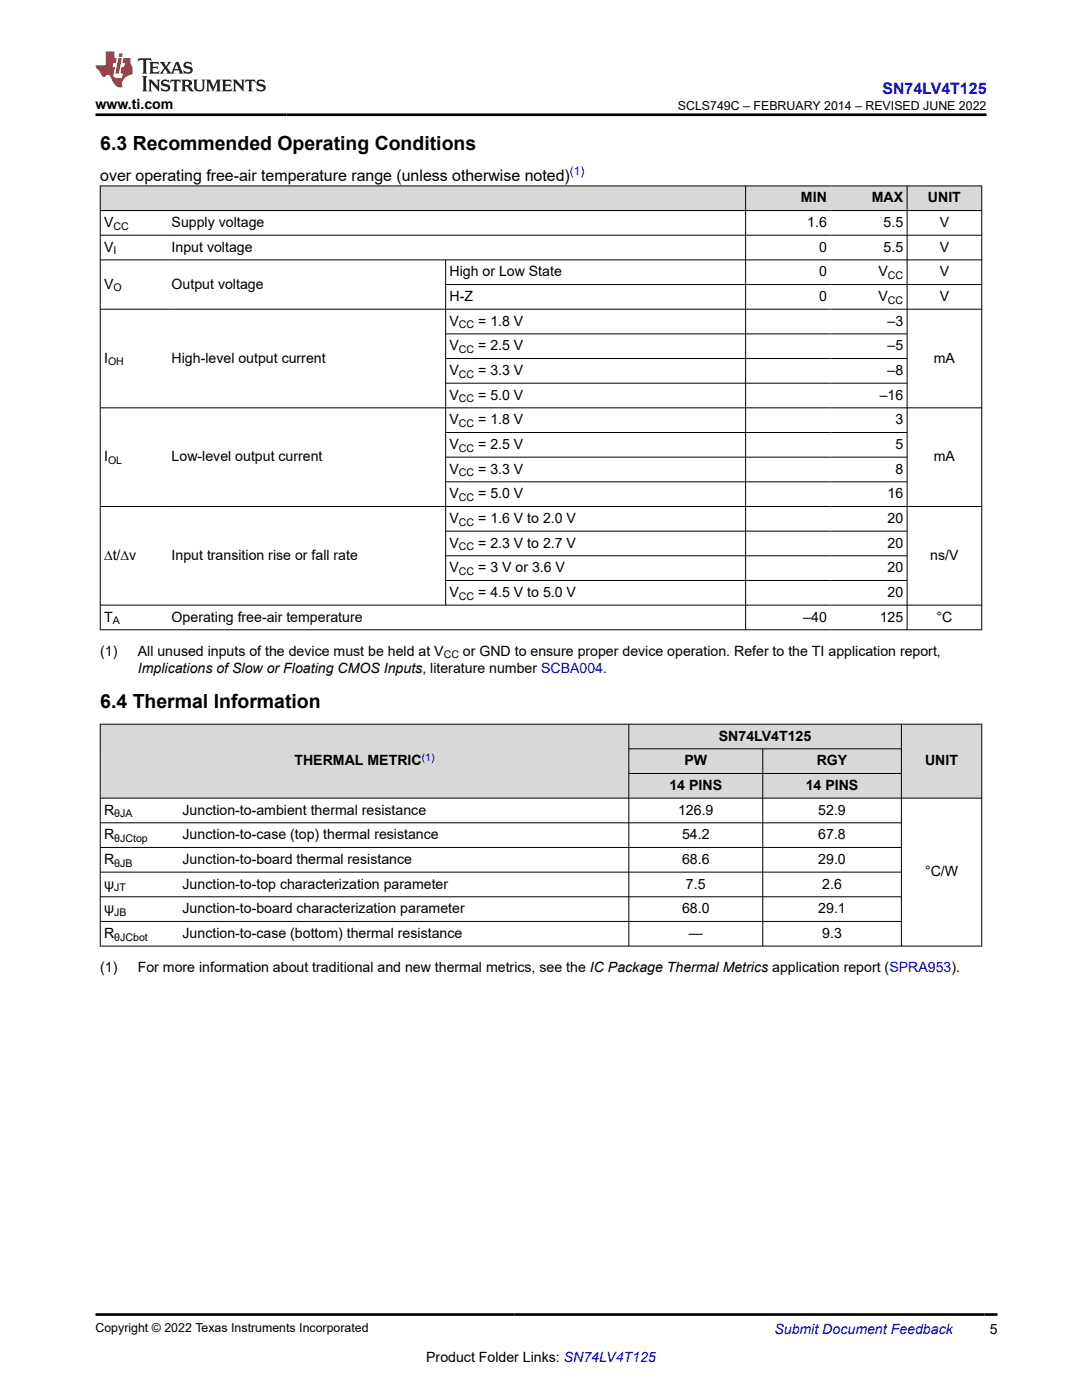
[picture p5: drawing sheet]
<svg xmlns="http://www.w3.org/2000/svg" width="216mm" height="279mm" viewBox="0 0 216 279" stroke-linecap="round" stroke-linejoin="round" font-family="sans-serif">
<defs><g id="words">
<g font-size="3.9">
<text x="20" y="29.9">6.3 Recommended Operating Conditions</text>
<text x="20" y="141.2">6.4 Thermal Information</text>
</g>
<text font-size="3.2" fill="#00f" x="176.1" y="18.7">SN74LV4T125</text>
<text font-size="3.2" x="20" y="36.1">over operating free-air temperature range (unless otherwise noted)</text>
<g font-size="2.8">
<text x="19.1" y="21.8">www.ti.com</text>
<text x="159.8" y="40.4">MIN</text>
<text x="174" y="40.4">MAX</text>
<text x="185.2" y="40.4">UNIT</text>
<text x="20.8" y="45.3">V</text>
<text x="34.2" y="45.3">Supply voltage</text>
<text x="161.1" y="45.3">1.6</text>
<text x="176.3" y="45.3">5.5</text>
<text x="187.5" y="45.3">V</text>
<text x="20.8" y="50.2">V</text>
<text x="34.2" y="50.2">Input voltage</text>
<text x="163.4" y="50.2">0</text>
<text x="176.3" y="50.2">5.5</text>
<text x="187.5" y="50.2">V</text>
<text x="20.8" y="57.6">V</text>
<text x="34.2" y="57.6">Output voltage</text>
<text x="89.7" y="55.1">High or Low State</text>
<text x="163.4" y="55.1">0</text>
<text x="175.3" y="55.1">V</text>
<text x="187.5" y="55.1">V</text>
<text x="89.7" y="60.1">H-Z</text>
<text x="89.7" y="65">V</text>
<text x="95.4" y="65">= 1.8 V</text>
<text x="163.4" y="60.1">0</text>
<text x="175.3" y="60.1">V</text>
<text x="177.1" y="65">–3</text>
<text x="187.5" y="60.1">V</text>
<text x="89.7" y="69.9">V</text>
<text x="95.4" y="69.9">= 2.5 V</text>
<text x="177.1" y="69.9">–5</text>
<text x="20.8" y="72.4">I</text>
<text x="34.2" y="72.4">High-level output current</text>
<text x="89.7" y="74.8">V</text>
<text x="95.4" y="74.8">= 3.3 V</text>
<text x="177.1" y="74.8">–8</text>
<text x="186.3" y="72.4">mA</text>
<text x="89.7" y="79.7">V</text>
<text x="95.4" y="79.7">= 5.0 V</text>
<text x="175.5" y="79.7">–16</text>
<text x="89.7" y="84.7">V</text>
<text x="89.7" y="89.6">V</text>
<text x="95.4" y="84.7">= 1.8 V</text>
<text x="95.4" y="89.6">= 2.5 V</text>
<text x="178.7" y="84.7">3</text>
<text x="178.7" y="89.6">5</text>
<text x="20.8" y="92.1">I</text>
<text x="34.2" y="92.1">Low-level output current</text>
<text x="89.7" y="94.5">V</text>
<text x="95.4" y="94.5">= 3.3 V</text>
<text x="178.7" y="94.5">8</text>
<text x="186.3" y="92.1">mA</text>
<text x="89.7" y="99.4">V</text>
<text x="95.4" y="99.4">= 5.0 V</text>
<text x="177.1" y="99.4">16</text>
<text x="89.7" y="104.4">V</text>
<text x="95.4" y="104.4">= 1.6 V to 2.0 V</text>
<text x="177.1" y="104.4">20</text>
<text x="20.8" y="111.7">∆t/∆v</text>
<text x="34.2" y="111.7">Input transition rise or fall rate</text>
<text x="89.7" y="109.3">V</text>
<text x="95.4" y="109.3">= 2.3 V to 2.7 V</text>
<text x="177.1" y="109.3">20</text>
<text x="185.6" y="111.7">ns/V</text>
<text x="89.7" y="114.2">V</text>
<text x="89.7" y="119.1">V</text>
<text x="95.4" y="114.2">= 3 V or 3.6 V</text>
<text x="95.4" y="119.1">= 4.5 V to 5.0 V</text>
<text x="177.1" y="114.2">20</text>
<text x="177.1" y="119.1">20</text>
<text x="20.8" y="124">T</text>
<text x="34.2" y="124">Operating free-air temperature</text>
<text x="160.3" y="124">–40</text>
<text x="175.5" y="124">125</text>
<text x="186.9" y="124">°C</text>
<text x="20" y="130.8">(1)</text>
<text x="27.5" y="130.8">All unused inputs of the device must be held at V</text>
<text x="92.4" y="130.8">or GND to ensure proper device operation. Refer to the TI application report,</text>
<text x="27.5" y="134.2">Implications of Slow or Floating CMOS Inputs, literature number SCBA004.</text>
<text x="143.4" y="147.8">SN74LV4T125</text>
<text x="58.7" y="152.7">THERMAL METRIC</text>
<text x="136.6" y="152.7">PW</text>
<text x="163" y="152.7">RGY</text>
<text x="184.6" y="152.7">UNIT</text>
<text x="133.6" y="157.6">14 PINS</text>
<text x="160.8" y="157.6">14 PINS</text>
<text x="20.8" y="162.6">R</text>
<text x="20.8" y="167.5">R</text>
<text x="36.4" y="162.6">Junction-to-ambient thermal resistance</text>
<text x="36.4" y="167.5">Junction-to-case (top) thermal resistance</text>
<text x="135.3" y="162.6">126.9</text>
<text x="136.1" y="167.5">54.2</text>
<text x="163.3" y="162.6">52.9</text>
<text x="163.3" y="167.5">67.8</text>
<text x="20.8" y="172.4">R</text>
<text x="36.4" y="172.4">Junction-to-board thermal resistance</text>
<text x="136.1" y="172.4">68.6</text>
<text x="163.3" y="172.4">29.0</text>
<text x="20.8" y="177.3">ψ</text>
<text x="36.4" y="177.3">Junction-to-top characterization parameter</text>
<text x="136.9" y="177.3">7.5</text>
<text x="164.1" y="177.3">2.6</text>
<text x="184.6" y="174.9">°C/W</text>
<text x="20.8" y="182.2">ψ</text>
<text x="36.4" y="182.2">Junction-to-board characterization parameter</text>
<text x="136.1" y="182.2">68.0</text>
<text x="163.3" y="182.2">29.1</text>
<text x="20.8" y="187.2">R</text>
<text x="36.4" y="187.2">Junction-to-case (bottom) thermal resistance</text>
<text x="137.4" y="187.2">—</text>
<text x="164.1" y="187.2">9.3</text>
<text x="20" y="194">(1)</text>
<text x="27.5" y="194">For more information about traditional and new thermal metrics, see the IC Package Thermal Metrics application report (SPRA953).</text>
<text x="197.5" y="266.1">5</text>
<text x="85" y="271.7">Product Folder Links: SN74LV4T125</text>
</g>
<text font-size="2.8" fill="#00f" x="154.5" y="266.2">Submit Document Feedback</text>
<g font-size="2.5">
<text x="135.3" y="21.9">SCLS749C – FEBRUARY 2014 – REVISED JUNE 2022</text>
<text x="19.1" y="265.9">Copyright © 2022 Texas Instruments Incorporated</text>
</g>
<text font-size="2.4" fill="#00f" x="113.7" y="35">(1)</text>
<g font-size="2.1">
<text x="22.6" y="45.9">CC</text>
<text x="22.6" y="50.8">I</text>
<text x="22.6" y="58.2">O</text>
<text x="177.2" y="55.7">CC</text>
<text x="91.6" y="65.5">CC</text>
<text x="177.2" y="60.6">CC</text>
<text x="91.6" y="70.5">CC</text>
<text x="21.6" y="72.9">OH</text>
<text x="91.6" y="75.4">CC</text>
<text x="91.6" y="80.3">CC</text>
<text x="91.6" y="85.2">CC</text>
<text x="21.6" y="92.6">OL</text>
<text x="91.6" y="90.2">CC</text>
<text x="91.6" y="95.1">CC</text>
<text x="91.6" y="100">CC</text>
<text x="91.6" y="104.9">CC</text>
<text x="91.6" y="109.8">CC</text>
<text x="91.6" y="114.8">CC</text>
<text x="91.6" y="119.7">CC</text>
<text x="22.5" y="124.6">A</text>
<text x="88.5" y="131.4">CC</text>
<text x="22.8" y="163.1">θJA</text>
<text x="22.8" y="168">θJCtop</text>
<text x="22.8" y="173">θJB</text>
<text x="22.8" y="177.9">JT</text>
<text x="22.8" y="182.8">JB</text>
<text x="22.8" y="187.7">θJCbot</text>
</g>
<text font-size="2.1" fill="#00f" x="84.1" y="151.8">(1)</text>
</g></defs>
<g fill="#d8d8d8">
<path d="M20 37.1h175.9v4.9h-175.9z" fill-rule="evenodd"/>
<path d="M20.1 37.2h128.6v4.8h-128.6z" fill-rule="evenodd"/>
<path d="M148.8 37.2h16.9v4.8h-16.9z" fill-rule="evenodd"/>
<path d="M165.7 37.2h15.2v4.8h-15.2z" fill-rule="evenodd"/>
<path d="M181.1 37.2h14.7v4.8h-14.7z" fill-rule="evenodd"/>
</g>
<g fill="none" stroke="#000" stroke-width=".2">
<path d="M19.9 37.1h176.1M20 37v88.7M148.8 37v88.7M181 37v88.7M195.9 37v88.7M19.9 42h176.1M19.9 46.9h176.1M19.9 51.9h176.1M88.9 51.9v68.9M88.9 56.8h107.1M19.9 61.7h176.1M88.9 66.6h92.2"/>
<path d="M88.9 71.6h92.2M88.9 76.5h92.2M19.9 81.4h176.1M88.9 86.3h92.2M88.9 91.2h92.2M88.9 96.2h92.2M19.9 101.1h176.1M88.9 106h92.2M88.9 110.9h92.2M88.9 115.8h92.2M19.9 120.8h176.1M19.9 125.7h176.1"/>
</g>
<g fill="#d8d8d8">
<path d="M20 144.5h175.9v4.9h-175.9z" fill-rule="evenodd"/>
<path d="M20.1 144.6h105.3v14.6h-105.3z" fill-rule="evenodd"/>
<path d="M125.5 144.6h54.3v4.8h-54.3z" fill-rule="evenodd"/>
<path d="M179.9 144.6h15.9v14.6h-15.9z" fill-rule="evenodd"/>
<path d="M125.5 149.5h26.6v4.8h-26.6z" fill-rule="evenodd"/>
<path d="M152.3 149.5h27.5v4.8h-27.5z" fill-rule="evenodd"/>
<path d="M125.5 154.4h26.6v4.8h-26.6z" fill-rule="evenodd"/>
<path d="M152.3 154.4h27.5v4.8h-27.5z" fill-rule="evenodd"/>
</g>
<g fill="none" stroke="#000" stroke-width=".2">
<path d="M19.9 144.5h176.1M19.9 159.3h176.1M20 144.5v44.4M125.5 144.5v44.4M125.5 149.4h54.4M125.5 154.4h54.4M152.2 149.4v39.5M179.9 144.5v44.4M195.9 144.5v44.4M19.9 164.2h160M19.9 169.1h160M19.9 174.1h160"/>
<path d="M19.9 179h160M19.9 183.9h160M196 188.8h-176.1"/>
</g>
<path d="M27.7 11.6l-.2 .6 .5-.2h.6v.1v2.2l-.2 .4h1l-.2-.4v-2.2v-.1h.5l.5 .2-.1-.6zM29.8 12.4l.2 .3v1.6l-.2 .4h1.9l.1-.6a1.08 1.08 0 0 1-1.3 .2v-.7h.6l.4 .2v-.7l-.4 .2h-.6v-.5l.2-.2a1 1 0 0 1 1 .3l-.1-.5zM31.8 12.4l1 1.1-1 1.2h.9l-.2-.2 .4-.8 .5 .8-.2 .2h1.6l-.2-.2 .1-.5h1l.1 .5-.1 .2h.9l-.2-.4-.8-1.9h-.5l-1 2.1-.8-1.1 .9-1h-.8l.2 .2-.5 .6-.3-.6 .1-.2zM35.2 12.8l.4 1h-.8zM36.8 12.5a.65 .65 0 0 0-.2 .7 .65 .65 0 0 0 .6 .5l.7 .1 .1 .3a.79 .79 0 0 1-.7 .4 .79 .79 0 0 1-.7-.5l.1 .7 .2-.1a.93 .93 0 0 0 1.1 0 .93 .93 0 0 0 .4-.9 1.46 1.46 0 0 0-1.2-.6l-.1-.3a1.09 1.09 0 0 1 1.2 .2l-.2-.6-.1 .1-.6-.2zM28.4 15.2l.2 .4v2.2l-.2 .4h1l-.2-.4v-2.2l.2-.4zM29.6 15.9l.2 .4v1.5l-.2 .4h.8l-.3-.4v-1.3l1.7 1.8v-2l.2-.4h-.8l.2 .2 .1 1.1-1.2-1.3zM32.3 16a.65 .65 0 0 0-.2 .8 .65 .65 0 0 0 .7 .4l.6 .2 .1 .2a.79 .79 0 0 1-.7 .4 .79 .79 0 0 1-.7-.5l.1 .7 .2-.1a.93 .93 0 0 0 1.1 .1 .93 .93 0 0 0 .4-1 1.46 1.46 0 0 0-1.2-.5l-.1-.4a1.09 1.09 0 0 1 1.2 .2l-.2-.6-.1 .1-.6-.1zM34.1 15.9l-.1 .6a.63 .63 0 0 1 .7-.3l.1 1.6-.3 .4h1l-.2-.4v-1.6a.66 .66 0 0 1 .8 .3l-.1-.6zM36.2 15.9l.2 .4v1.5l-.2 .4h.9l-.2-.2v-.7h.5l.1 .2a.79 .79 0 0 0 1.2 .6l-1-.9a.61 .61 0 0 0 .6-.6 .61 .61 0 0 0-.5-.7zM36.9 16.2h.2a.47 .47 0 0 1 .5 .1 .47 .47 0 0 1 .1 .5l-.2 .1-.6 .1zM38.5 15.9l.2 .2a2.27 2.27 0 0 0 .4 2 1.04 1.04 0 0 0 1.7-.7v-1.3l.2-.2h-.8l.2 .4v1.1a.6 .6 0 0 1-.6 .6 .6 .6 0 0 1-.6-.6v-1.1l.3-.4zM41.1 15.9l.2 .4v1.5l-.2 .4h.7l-.2-.4v-1.4l.9 1.9 .8-1.9v1.4l-.2 .4h1l-.3-.4v-1.5l.3-.4h-.8l-.7 1.5-.7-1.5zM44.3 15.9l.2 .4v1.5l-.2 .4h1.9l.1-.6a1.09 1.09 0 0 1-1.3 .2v-.7h.6l.4 .2v-.6l-.4 .2h-.6v-.6l.2-.1a1.01 1.01 0 0 1 1 .3l-.1-.6zM46.4 15.9l.3 .4v1.5l-.3 .4h.8l-.2-.4v-1.3l1.6 1.8v-2l.2-.4h-.7l.2 .2v1.1l-1.2-1.3zM49 15.9l-.1 .6a.63 .63 0 0 1 .8-.3v1.6l-.3 .4h1l-.2-.4v-1.6a.66 .66 0 0 1 .8 .3l-.1-.6zM51.4 16a.65 .65 0 0 0-.2 .8 .65 .65 0 0 0 .6 .4l.6 .2 .2 .2a.79 .79 0 0 1-.8 .4 .79 .79 0 0 1-.6-.5l.1 .7 .2-.1a.93 .93 0 0 0 1 .1 .93 .93 0 0 0 .5-1 1.46 1.46 0 0 0-1.3-.5l-.1-.4a1.09 1.09 0 0 1 1.3 .2l-.2-.6-.2 .1-.5-.1z" fill="#231f20"/>
<path d="M21.1 10.3v2.7h-2.1l.1 .4 .9 1a.95 .95 0 0 0 .9 .9 .59 .59 0 0 1 .6-.4 .59 .59 0 0 1 .5 .3l.4 .8a1.59 1.59 0 0 0 2.1 1.4 1.61 1.61 0 0 1 1-2.3l1-.3-.1-1.5a1.59 1.59 0 0 1-.4-1.7h-1.4l-.2 .9h.5l-.1 .9h-.5l-.2 .9v.3l.4 .1-.2 .9h-.6a.73 .73 0 0 1-1.1-.7l.3-1.5h-.5l.2-.9h.5l.2-.9h-.5v-1.3zM23.6 11.6l-.6 3.1h.7l.6-3.1zM23.8 10.7l-.1 .6h.7l.1-.6z" fill="#ed1c24"/>
<path d="M19.1 22.9h177.8M19.1 262.3h179.9" fill="none" stroke="#000" stroke-width=".53"/>
<use href="#words"/>
</svg>
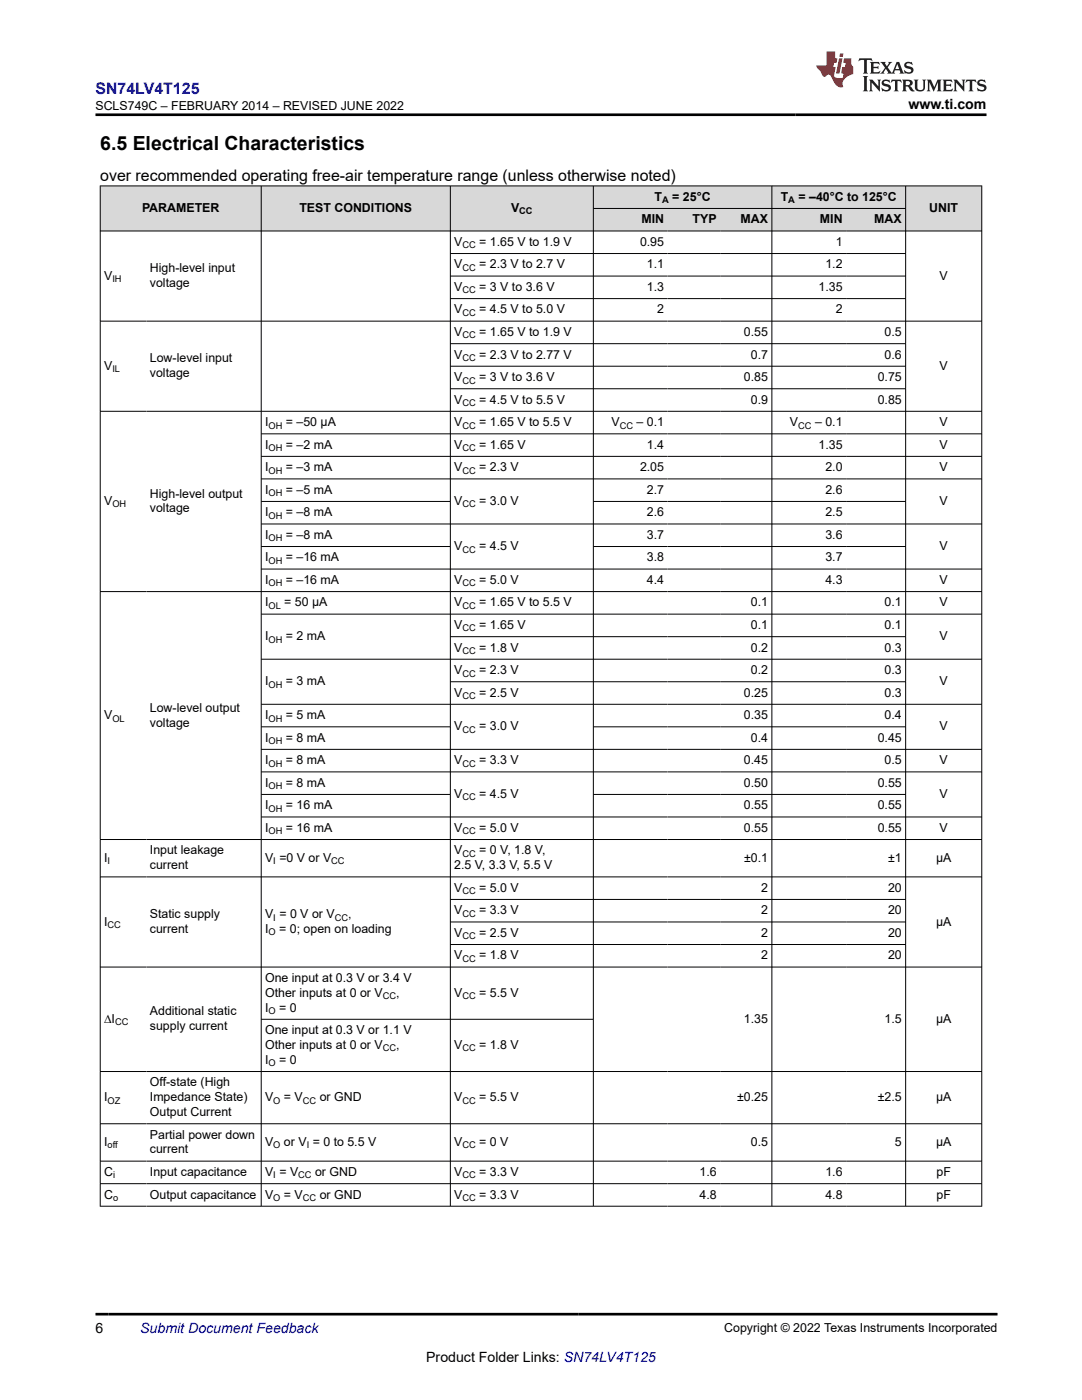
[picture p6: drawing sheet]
<svg xmlns="http://www.w3.org/2000/svg" width="216mm" height="279mm" viewBox="0 0 216 279" stroke-linecap="round" stroke-linejoin="round" font-family="sans-serif">
<defs><g id="words">
<text font-size="3.9" x="20" y="29.9">6.5 Electrical Characteristics</text>
<text font-size="3.2" fill="#00f" x="19.1" y="18.7">SN74LV4T125</text>
<text font-size="3.2" x="20" y="36.1">over recommended operating free-air temperature range (unless otherwise noted)</text>
<g font-size="2.8">
<text x="181.3" y="21.8">www.ti.com</text>
<text x="19.1" y="266.1">6</text>
<text x="85" y="271.7">Product Folder Links: SN74LV4T125</text>
</g>
<text font-size="2.8" fill="#00f" x="28" y="266.1">Submit Document Feedback</text>
<g font-size="2.5">
<text x="19" y="21.9">SCLS749C – FEBRUARY 2014 – REVISED JUNE 2022</text>
<text x="130.6" y="40.1">T</text>
<text x="134.2" y="40.1">= 25°C</text>
<text x="155.8" y="40.1">T</text>
<text x="159.3" y="40.1">= –40°C to 125°C</text>
<text x="28.3" y="42.3">PARAMETER</text>
<text x="59.7" y="42.3">TEST CONDITIONS</text>
<text x="102" y="42.3">V</text>
<text x="128" y="44.6">MIN</text>
<text x="138.2" y="44.6">TYP</text>
<text x="147.8" y="44.6">MAX</text>
<text x="163.6" y="44.6">MIN</text>
<text x="174.5" y="44.6">MAX</text>
<text x="185.4" y="42.3">UNIT</text>
<text x="90.6" y="49.1">V</text>
<text x="90.6" y="53.6">V</text>
<text x="95.6" y="49.1">= 1.65 V to 1.9 V</text>
<text x="95.6" y="53.6">= 2.3 V to 2.7 V</text>
<text x="127.7" y="49.1">0.95</text>
<text x="129.1" y="53.6">1.1</text>
<text x="164.7" y="53.6">1.2</text>
<text x="166.8" y="49.1">1</text>
<text x="20.8" y="55.8">V</text>
<text x="29.9" y="54.3">High-level input</text>
<text x="29.9" y="57.3">voltage</text>
<text x="90.6" y="58.1">V</text>
<text x="95.6" y="58.1">= 3 V to 3.6 V</text>
<text x="129.1" y="58.1">1.3</text>
<text x="163.3" y="58.1">1.35</text>
<text x="187.5" y="55.8">V</text>
<text x="90.6" y="62.6">V</text>
<text x="95.6" y="62.6">= 4.5 V to 5.0 V</text>
<text x="131.1" y="62.6">2</text>
<text x="166.8" y="62.6">2</text>
<text x="90.6" y="67.1">V</text>
<text x="90.6" y="71.5">V</text>
<text x="95.6" y="67.1">= 1.65 V to 1.9 V</text>
<text x="95.6" y="71.5">= 2.3 V to 2.77 V</text>
<text x="148.4" y="67.1">0.55</text>
<text x="149.8" y="71.5">0.7</text>
<text x="176.5" y="67.1">0.5</text>
<text x="176.5" y="71.5">0.6</text>
<text x="20.8" y="73.8">V</text>
<text x="29.9" y="72.3">Low-level input</text>
<text x="29.9" y="75.3">voltage</text>
<text x="90.6" y="76">V</text>
<text x="95.6" y="76">= 3 V to 3.6 V</text>
<text x="148.4" y="76">0.85</text>
<text x="175.1" y="76">0.75</text>
<text x="187.5" y="73.8">V</text>
<text x="90.6" y="80.5">V</text>
<text x="95.6" y="80.5">= 4.5 V to 5.5 V</text>
<text x="149.8" y="80.5">0.9</text>
<text x="175.1" y="80.5">0.85</text>
<text x="52.9" y="85">I</text>
<text x="52.9" y="89.5">I</text>
<text x="57" y="85">= –50 µA</text>
<text x="57" y="89.5">= –2 mA</text>
<text x="90.6" y="85">V</text>
<text x="90.6" y="89.5">V</text>
<text x="95.6" y="85">= 1.65 V to 5.5 V</text>
<text x="95.6" y="89.5">= 1.65 V</text>
<text x="122" y="85">V</text>
<text x="127" y="85">– 0.1</text>
<text x="129.1" y="89.5">1.4</text>
<text x="157.6" y="85">V</text>
<text x="162.6" y="85">– 0.1</text>
<text x="163.3" y="89.5">1.35</text>
<text x="187.5" y="85">V</text>
<text x="187.5" y="89.5">V</text>
<text x="52.9" y="94">I</text>
<text x="57" y="94">= –3 mA</text>
<text x="90.6" y="94">V</text>
<text x="95.6" y="94">= 2.3 V</text>
<text x="127.7" y="94">2.05</text>
<text x="164.7" y="94">2.0</text>
<text x="187.5" y="94">V</text>
<text x="20.8" y="100.8">V</text>
<text x="29.9" y="99.3">High-level output</text>
<text x="52.9" y="98.5">I</text>
<text x="57" y="98.5">= –5 mA</text>
<text x="90.6" y="100.8">V</text>
<text x="95.6" y="100.8">= 3.0 V</text>
<text x="129.1" y="98.5">2.7</text>
<text x="164.7" y="98.5">2.6</text>
<text x="187.5" y="100.8">V</text>
<text x="29.9" y="102.3">voltage</text>
<text x="52.9" y="103">I</text>
<text x="52.9" y="107.5">I</text>
<text x="57" y="103">= –8 mA</text>
<text x="57" y="107.5">= –8 mA</text>
<text x="129.1" y="103">2.6</text>
<text x="129.1" y="107.5">3.7</text>
<text x="164.7" y="103">2.5</text>
<text x="164.7" y="107.5">3.6</text>
<text x="52.9" y="112">I</text>
<text x="57" y="112">= –16 mA</text>
<text x="90.6" y="109.8">V</text>
<text x="95.6" y="109.8">= 4.5 V</text>
<text x="129.1" y="112">3.8</text>
<text x="164.7" y="112">3.7</text>
<text x="187.5" y="109.8">V</text>
<text x="52.9" y="116.5">I</text>
<text x="57" y="116.5">= –16 mA</text>
<text x="90.6" y="116.5">V</text>
<text x="95.6" y="116.5">= 5.0 V</text>
<text x="129.1" y="116.5">4.4</text>
<text x="164.7" y="116.5">4.3</text>
<text x="187.5" y="116.5">V</text>
<text x="52.9" y="121">I</text>
<text x="56.7" y="121">= 50 µA</text>
<text x="90.6" y="121">V</text>
<text x="90.6" y="125.5">V</text>
<text x="95.6" y="121">= 1.65 V to 5.5 V</text>
<text x="95.6" y="125.5">= 1.65 V</text>
<text x="149.8" y="121">0.1</text>
<text x="149.8" y="125.5">0.1</text>
<text x="176.5" y="121">0.1</text>
<text x="176.5" y="125.5">0.1</text>
<text x="187.5" y="121">V</text>
<text x="52.9" y="127.8">I</text>
<text x="57" y="127.8">= 2 mA</text>
<text x="90.6" y="130">V</text>
<text x="95.6" y="130">= 1.8 V</text>
<text x="149.8" y="130">0.2</text>
<text x="176.5" y="130">0.3</text>
<text x="187.5" y="127.8">V</text>
<text x="52.9" y="136.8">I</text>
<text x="57" y="136.8">= 3 mA</text>
<text x="90.6" y="134.5">V</text>
<text x="95.6" y="134.5">= 2.3 V</text>
<text x="149.8" y="134.5">0.2</text>
<text x="176.5" y="134.5">0.3</text>
<text x="187.5" y="136.8">V</text>
<text x="20.8" y="143.5">V</text>
<text x="29.9" y="142">Low-level output</text>
<text x="52.9" y="143.5">I</text>
<text x="57" y="143.5">= 5 mA</text>
<text x="90.6" y="139">V</text>
<text x="95.6" y="139">= 2.5 V</text>
<text x="148.4" y="139">0.25</text>
<text x="148.4" y="143.5">0.35</text>
<text x="176.5" y="139">0.3</text>
<text x="176.5" y="143.5">0.4</text>
<text x="29.9" y="145">voltage</text>
<text x="52.9" y="148">I</text>
<text x="57" y="148">= 8 mA</text>
<text x="90.6" y="145.8">V</text>
<text x="95.6" y="145.8">= 3.0 V</text>
<text x="149.8" y="148">0.4</text>
<text x="175.1" y="148">0.45</text>
<text x="187.5" y="145.8">V</text>
<text x="52.9" y="152.5">I</text>
<text x="57" y="152.5">= 8 mA</text>
<text x="90.6" y="152.5">V</text>
<text x="95.6" y="152.5">= 3.3 V</text>
<text x="148.4" y="152.5">0.45</text>
<text x="176.5" y="152.5">0.5</text>
<text x="187.5" y="152.5">V</text>
<text x="52.9" y="157">I</text>
<text x="52.9" y="161.5">I</text>
<text x="57" y="157">= 8 mA</text>
<text x="57" y="161.5">= 16 mA</text>
<text x="90.6" y="159.3">V</text>
<text x="95.6" y="159.3">= 4.5 V</text>
<text x="148.4" y="157">0.50</text>
<text x="148.4" y="161.5">0.55</text>
<text x="175.1" y="157">0.55</text>
<text x="175.1" y="161.5">0.55</text>
<text x="187.5" y="159.3">V</text>
<text x="52.9" y="166">I</text>
<text x="57" y="166">= 16 mA</text>
<text x="90.6" y="166">V</text>
<text x="95.6" y="166">= 5.0 V</text>
<text x="148.4" y="166">0.55</text>
<text x="175.1" y="166">0.55</text>
<text x="187.5" y="166">V</text>
<text x="20.8" y="172">I</text>
<text x="29.9" y="170.5">Input leakage</text>
<text x="29.9" y="173.5">current</text>
<text x="52.9" y="172">V =0 V or V</text>
<text x="90.6" y="170.5">V</text>
<text x="90.6" y="173.5">2.5 V, 3.3 V, 5.5 V</text>
<text x="95.6" y="170.5">= 0 V, 1.8 V,</text>
<text x="148.5" y="172">±0.1</text>
<text x="177.2" y="172">±1</text>
<text x="186.8" y="172">μA</text>
<text x="90.6" y="178">V</text>
<text x="95.6" y="178">= 5.0 V</text>
<text x="151.9" y="178">2</text>
<text x="177.2" y="178">20</text>
<text x="20.8" y="184.7">I</text>
<text x="29.9" y="183.2">Static supply</text>
<text x="52.9" y="183.2">V = 0 V or V</text>
<text x="69.5" y="183.2">,</text>
<text x="90.6" y="182.5">V</text>
<text x="95.6" y="182.5">= 3.3 V</text>
<text x="151.9" y="182.5">2</text>
<text x="177.2" y="182.5">20</text>
<text x="186.8" y="184.7">μA</text>
<text x="29.9" y="186.2">current</text>
<text x="52.9" y="186.2">I</text>
<text x="55.7" y="186.2">= 0; open on loading</text>
<text x="90.6" y="187">V</text>
<text x="90.6" y="191.5">V</text>
<text x="95.6" y="187">= 2.5 V</text>
<text x="95.6" y="191.5">= 1.8 V</text>
<text x="151.9" y="187">2</text>
<text x="151.9" y="191.5">2</text>
<text x="177.2" y="187">20</text>
<text x="177.2" y="191.5">20</text>
<text x="52.9" y="196">One input at 0.3 V or 3.4 V</text>
<text x="29.9" y="202.7">Additional static</text>
<text x="52.9" y="201.9">I</text>
<text x="52.9" y="198.9">Other inputs at 0 or V</text>
<text x="55.7" y="201.9">= 0</text>
<text x="79" y="198.9">,</text>
<text x="90.6" y="198.9">V</text>
<text x="95.6" y="198.9">= 5.5 V</text>
<text x="20.8" y="204.1">∆I</text>
<text x="29.9" y="205.6">supply current</text>
<text x="52.9" y="206.4">One input at 0.3 V or 1.1 V</text>
<text x="52.9" y="209.3">Other inputs at 0 or V</text>
<text x="79" y="209.3">,</text>
<text x="90.6" y="209.3">V</text>
<text x="95.6" y="209.3">= 1.8 V</text>
<text x="148.4" y="204.1">1.35</text>
<text x="176.5" y="204.1">1.5</text>
<text x="186.8" y="204.1">μA</text>
<text x="52.9" y="212.3">I</text>
<text x="55.7" y="212.3">= 0</text>
<text x="20.8" y="219.8">I</text>
<text x="29.9" y="216.8">Off-state (High</text>
<text x="29.9" y="219.8">Impedance State)</text>
<text x="52.9" y="219.8">V</text>
<text x="56.7" y="219.8">= V</text>
<text x="63.8" y="219.8">or GND</text>
<text x="90.6" y="219.8">V</text>
<text x="95.6" y="219.8">= 5.5 V</text>
<text x="147.1" y="219.8">±0.25</text>
<text x="175.2" y="219.8">±2.5</text>
<text x="186.8" y="219.8">μA</text>
<text x="29.9" y="222.7">Output Current</text>
<text x="29.9" y="227.2">Partial power down</text>
<text x="20.8" y="228.7">I</text>
<text x="29.9" y="230.2">current</text>
<text x="52.9" y="228.7">V</text>
<text x="56.7" y="228.7">or V = 0 to 5.5 V</text>
<text x="90.6" y="228.7">V</text>
<text x="95.6" y="228.7">= 0 V</text>
<text x="149.8" y="228.7">0.5</text>
<text x="178.6" y="228.7">5</text>
<text x="186.8" y="228.7">μA</text>
<text x="20.8" y="234.7">C</text>
<text x="20.8" y="239.2">C</text>
<text x="29.9" y="234.7">Input capacitance</text>
<text x="29.9" y="239.2">Output capacitance</text>
<text x="52.9" y="234.7">V = V</text>
<text x="52.9" y="239.2">V</text>
<text x="56.7" y="239.2">= V</text>
<text x="62.9" y="234.7">or GND</text>
<text x="63.8" y="239.2">or GND</text>
<text x="90.6" y="234.7">V</text>
<text x="90.6" y="239.2">V</text>
<text x="95.6" y="234.7">= 3.3 V</text>
<text x="95.6" y="239.2">= 3.3 V</text>
<text x="139.6" y="234.7">1.6</text>
<text x="139.6" y="239.2">4.8</text>
<text x="164.7" y="234.7">1.6</text>
<text x="164.7" y="239.2">4.8</text>
<text x="186.9" y="234.7">pF</text>
<text x="186.9" y="239.2">pF</text>
<text x="144.5" y="265.8">Copyright © 2022 Texas Instruments Incorporated</text>
</g>
<g font-size="1.9">
<text x="132.1" y="40.6">A</text>
<text x="157.3" y="40.6">A</text>
<text x="103.6" y="42.8">CC</text>
<text x="92.3" y="49.6">CC</text>
<text x="22.4" y="56.3">IH</text>
<text x="92.3" y="54.1">CC</text>
<text x="92.3" y="58.5">CC</text>
<text x="92.3" y="63">CC</text>
<text x="92.3" y="67.5">CC</text>
<text x="22.4" y="74.3">IL</text>
<text x="92.3" y="72">CC</text>
<text x="92.3" y="76.5">CC</text>
<text x="92.3" y="81">CC</text>
<text x="53.6" y="85.5">OH</text>
<text x="92.3" y="85.5">CC</text>
<text x="123.7" y="85.5">CC</text>
<text x="159.3" y="85.5">CC</text>
<text x="53.6" y="90">OH</text>
<text x="53.6" y="94.5">OH</text>
<text x="92.3" y="90">CC</text>
<text x="92.3" y="94.5">CC</text>
<text x="22.4" y="101.3">OH</text>
<text x="53.6" y="99">OH</text>
<text x="92.3" y="101.3">CC</text>
<text x="53.6" y="103.5">OH</text>
<text x="53.6" y="108">OH</text>
<text x="53.6" y="112.5">OH</text>
<text x="92.3" y="110.3">CC</text>
<text x="53.6" y="117">OH</text>
<text x="92.3" y="117">CC</text>
<text x="53.6" y="121.5">OL</text>
<text x="92.3" y="121.5">CC</text>
<text x="53.6" y="128.3">OH</text>
<text x="92.3" y="126">CC</text>
<text x="92.3" y="130.5">CC</text>
<text x="53.6" y="137.3">OH</text>
<text x="92.3" y="135">CC</text>
<text x="92.3" y="139.5">CC</text>
<text x="22.4" y="144">OL</text>
<text x="53.6" y="144">OH</text>
<text x="53.6" y="148.5">OH</text>
<text x="92.3" y="146.3">CC</text>
<text x="53.6" y="153">OH</text>
<text x="92.3" y="153">CC</text>
<text x="53.6" y="157.5">OH</text>
<text x="92.3" y="159.8">CC</text>
<text x="53.6" y="162">OH</text>
<text x="53.6" y="166.5">OH</text>
<text x="92.3" y="166.5">CC</text>
<text x="21.5" y="172.5">I</text>
<text x="54.5" y="172.5">I</text>
<text x="66.1" y="172.5">CC</text>
<text x="92.3" y="171">CC</text>
<text x="92.3" y="178.5">CC</text>
<text x="21.5" y="185.2">CC</text>
<text x="54.5" y="183.7">I</text>
<text x="66.8" y="183.7">CC</text>
<text x="92.3" y="183">CC</text>
<text x="53.6" y="186.7">O</text>
<text x="92.3" y="187.5">CC</text>
<text x="92.3" y="192">CC</text>
<text x="53.6" y="202.4">O</text>
<text x="76.4" y="199.4">CC</text>
<text x="92.3" y="199.4">CC</text>
<text x="23" y="204.6">CC</text>
<text x="76.4" y="209.8">CC</text>
<text x="92.3" y="209.8">CC</text>
<text x="53.6" y="212.8">O</text>
<text x="21.5" y="220.3">OZ</text>
<text x="54.5" y="220.3">O</text>
<text x="60.4" y="220.3">CC</text>
<text x="92.3" y="220.3">CC</text>
<text x="21.5" y="229.2">off</text>
<text x="54.5" y="229.2">O</text>
<text x="61.2" y="229.2">I</text>
<text x="92.3" y="229.2">CC</text>
<text x="22.6" y="235.2">i</text>
<text x="22.6" y="239.7">o</text>
<text x="54.5" y="235.2">I</text>
<text x="54.5" y="239.7">O</text>
<text x="59.5" y="235.2">CC</text>
<text x="60.4" y="239.7">CC</text>
<text x="92.3" y="235.2">CC</text>
<text x="92.3" y="239.7">CC</text>
</g>
</g></defs>
<g fill="#d8d8d8">
<path d="M20 37.1h175.9v4.5h-175.9z" fill-rule="evenodd"/>
<path d="M20.1 37.2h32v8.8h-32z" fill-rule="evenodd"/>
<path d="M52.2 37.2h37.6v8.8h-37.6z" fill-rule="evenodd"/>
<path d="M89.9 37.2h28.4v8.8h-28.4z" fill-rule="evenodd"/>
<path d="M118.5 37.2h35.5v4.3h-35.5z" fill-rule="evenodd"/>
<path d="M154.1 37.2h26.6v4.3h-26.6z" fill-rule="evenodd"/>
<path d="M180.8 37.2h15v8.8h-15z" fill-rule="evenodd"/>
<path d="M118.5 41.7h14.7v4.3h-14.7z" fill-rule="evenodd"/>
<path d="M133.2 41.7h10.5v4.3h-10.5z" fill-rule="evenodd"/>
<path d="M143.7 41.7h10.3v4.3h-10.3z" fill-rule="evenodd"/>
<path d="M154.1 41.7h14.7v4.3h-14.7z" fill-rule="evenodd"/>
<path d="M168.8 41.7h11.9v4.3h-11.9z" fill-rule="evenodd"/>
</g>
<g fill="none" stroke="#000" stroke-width=".2">
<path d="M19.9 37.1h176.1M20 37v203.8M52.1 37v203.8M89.9 37v203.8M118.4 37v203.8M154 37v203.8M180.7 37v203.8M195.9 37v203.8M19.9 46.1h176.1M89.9 50.6h90.9M89.9 55.1h90.9M89.9 59.6h90.9"/>
<path d="M118.4 41.6h62.4M19.9 64.1h176.1M89.9 68.6h90.9M89.9 73.1h90.9M89.9 77.6h90.9M19.9 82.1h176.1M52.1 86.6h143.9M52.1 91.1h143.9M52.1 95.6h143.9M19.9 118.1h176.1M52.1 100.1h37.8M52.1 109.1h37.8"/>
<path d="M52.1 113.6h143.9M118.4 100.1h62.4M118.4 109.1h62.4M196 104.6h-143.9M52.1 122.6h143.9M52.1 131.6h143.9M89.9 127.1h90.9M89.9 136.1h90.9M52.1 140.6h143.9M52.1 145.1h37.8M52.1 149.6h143.9M52.1 154h143.9"/>
<path d="M52.1 158.5h37.8M118.4 145.1h62.4M118.4 158.5h62.4M19.9 167.5h176.1M19.9 175h176.1M52.1 163h143.9M89.9 179.5h90.9M19.9 193h176.1M89.9 184h90.9M89.9 188.5h90.9M19.9 213.8h176.1M52.1 203.4h66.4"/>
<path d="M19.9 224.3h176.1M19.9 231.7h176.1M19.9 236.2h176.1M19.9 240.7h176.1"/>
</g>
<path d="M171.5 11.6l-.2 .6 .5-.2h.6v.1v2.2l-.2 .4h1l-.2-.4v-2.2v-.1h.5l.6 .2-.2-.6zM173.6 12.4l.2 .3v1.6l-.2 .4h1.9l.1-.6a1.08 1.08 0 0 1-1.3 .2v-.7h.6l.4 .2v-.7l-.4 .2h-.6v-.5l.2-.2a1 1 0 0 1 1 .3l-.1-.5zM175.7 12.4l.9 1.1-1 1.2h.9l-.2-.2 .5-.8 .4 .8-.2 .2h1.6l-.2-.2 .2-.5h.9l.1 .5-.1 .2h.9l-.2-.4-.8-1.9h-.5l-.9 2.1-.9-1.1 .9-1h-.8l.2 .2-.4 .6-.4-.6 .2-.2zM179 12.8l.4 1h-.7zM180.7 12.5a.65 .65 0 0 0-.2 .7 .65 .65 0 0 0 .6 .5l.6 .1 .1 .3a.79 .79 0 0 1-.7 .4 .79 .79 0 0 1-.7-.5l.1 .7 .2-.1a.93 .93 0 0 0 1.1 0 .93 .93 0 0 0 .4-.9 1.46 1.46 0 0 0-1.2-.6l-.1-.3a1.09 1.09 0 0 1 1.2 .2l-.2-.6-.1 .1-.5-.2zM172.2 15.2l.2 .4v2.2l-.2 .4h1l-.2-.4v-2.2l.2-.4zM173.4 15.9l.2 .4v1.5l-.2 .4h.8l-.3-.4 .1-1.3 1.6 1.8v-2l.2-.4h-.7l.1 .2 .1 1.1-1.2-1.3zM176.2 16a.65 .65 0 0 0-.2 .8 .65 .65 0 0 0 .6 .4l.6 .2 .1 .2a.79 .79 0 0 1-.7 .4 .79 .79 0 0 1-.7-.5l.1 .7 .2-.1a.93 .93 0 0 0 1.1 .1 .93 .93 0 0 0 .4-1 1.46 1.46 0 0 0-1.2-.5l-.1-.4a1.09 1.09 0 0 1 1.2 .2l-.1-.6-.2 .1-.5-.1zM177.9 15.9l-.1 .6a.63 .63 0 0 1 .8-.3v1.6l-.3 .4h1l-.2-.4v-1.6a.66 .66 0 0 1 .8 .3l-.1-.6zM180 15.9l.2 .4v1.5l-.2 .4h1l-.2-.2-.1-.7h.5l.1 .2a.79 .79 0 0 0 1.2 .6l-1-.9a.61 .61 0 0 0 .6-.6 .61 .61 0 0 0-.5-.7zM180.8 16.2h.1a.47 .47 0 0 1 .5 .1 .47 .47 0 0 1 .1 .5l-.1 .1-.7 .1zM182.3 15.9l.2 .2a2.27 2.27 0 0 0 .4 2 1.04 1.04 0 0 0 1.7-.7v-1.3l.2-.2h-.8l.2 .4v1.1a.6 .6 0 0 1-.6 .6 .6 .6 0 0 1-.6-.6v-1.1l.3-.4zM184.9 15.9l.2 .4v1.5l-.2 .4h.8l-.3-.4v-1.4l.9 1.9 .9-1.9v1.4l-.3 .4h1l-.2-.4v-1.5l.2-.4h-.8l-.7 1.5-.6-1.5zM188.1 15.9l.2 .4v1.5l-.2 .4h1.9l.1-.6a1.09 1.09 0 0 1-1.3 .2v-.7h.6l.4 .2v-.6l-.4 .2h-.6v-.6l.2-.1a1.01 1.01 0 0 1 1 .3l-.1-.6zM190.2 15.9l.3 .4v1.5l-.3 .4h.8l-.2-.4v-1.3l1.6 1.8v-2l.2-.4h-.7l.2 .2v1.1l-1.2-1.3zM192.8 15.9l-.1 .6a.63 .63 0 0 1 .8-.3v1.6l-.3 .4h1l-.2-.4v-1.6a.66 .66 0 0 1 .8 .3l-.1-.6zM195.2 16a.65 .65 0 0 0-.2 .8 .65 .65 0 0 0 .6 .4l.6 .2 .2 .2a.79 .79 0 0 1-.7 .4 .79 .79 0 0 1-.7-.5l.1 .7 .2-.1a.93 .93 0 0 0 1 .1 .93 .93 0 0 0 .5-1 1.46 1.46 0 0 0-1.3-.5v-.4a1.09 1.09 0 0 1 1.2 .2l-.2-.6-.2 .1-.5-.1z" fill="#231f20"/>
<path d="M164.9 10.3v2.7h-2l.1 .4 .8 1a.95 .95 0 0 0 1 .9 .59 .59 0 0 1 .5-.4 .59 .59 0 0 1 .5 .3l.4 .8a1.59 1.59 0 0 0 2.1 1.4 1.61 1.61 0 0 1 1-2.3l1-.3-.1-1.5a1.59 1.59 0 0 1-.3-1.7h-1.5l-.2 .9h.6l-.2 .9h-.5l-.2 .9v.3l.4 .1-.1 .9h-.7a.73 .73 0 0 1-1-.7l.3-1.5h-.5l.1-.9h.5l.2-.9h-.5v-1.3zM167.4 11.6l-.6 3.1h.7l.6-3.1zM167.6 10.7l-.1 .6h.7l.1-.6z" fill="#ed1c24"/>
<path d="M19.1 22.9h177.8M19.1 262.3h179.9" fill="none" stroke="#000" stroke-width=".53"/>
<use href="#words"/>
</svg>
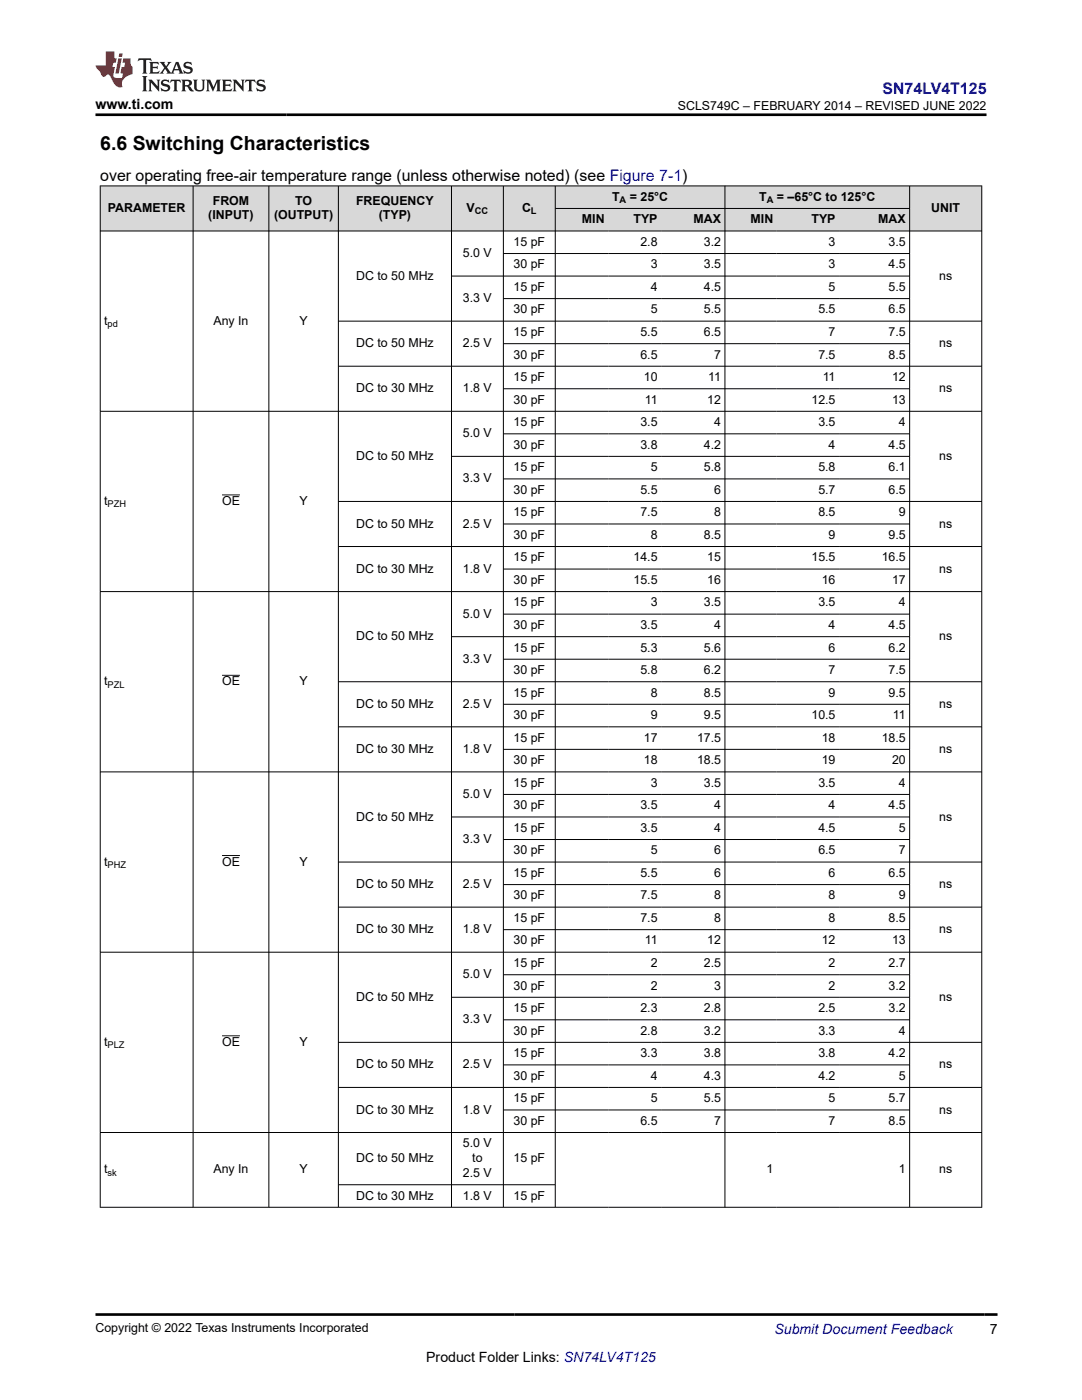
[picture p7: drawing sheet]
<svg xmlns="http://www.w3.org/2000/svg" width="216mm" height="279mm" viewBox="0 0 216 279" stroke-linecap="round" stroke-linejoin="round" font-family="sans-serif">
<defs><g id="words">
<text font-size="3.9" x="20" y="29.9">6.6 Switching Characteristics</text>
<text font-size="3.2" fill="#00f" x="176.1" y="18.7">SN74LV4T125</text>
<text font-size="3.2" x="20" y="36.1">over operating free-air temperature range (unless otherwise noted) (see Figure 7-1)</text>
<g font-size="2.8">
<text x="19.1" y="21.8">www.ti.com</text>
<text x="197.5" y="266.1">7</text>
<text x="85" y="271.7">Product Folder Links: SN74LV4T125</text>
</g>
<text font-size="2.8" fill="#00f" x="154.5" y="266.2">Submit Document Feedback</text>
<g font-size="2.5">
<text x="135.3" y="21.9">SCLS749C – FEBRUARY 2014 – REVISED JUNE 2022</text>
<text x="42.5" y="40.8">FROM</text>
<text x="58.9" y="40.8">TO</text>
<text x="71.1" y="40.8">FREQUENCY</text>
<text x="122.1" y="40.1">T</text>
<text x="125.7" y="40.1">= 25°C</text>
<text x="151.5" y="40.1">T</text>
<text x="155" y="40.1">= –65°C to 125°C</text>
<text x="21.5" y="42.3">PARAMETER</text>
<text x="41.6" y="43.8">(INPUT)</text>
<text x="54.7" y="43.8">(OUTPUT)</text>
<text x="75.6" y="43.8">(TYP)</text>
<text x="93.1" y="42.3">V</text>
<text x="104.2" y="42.3">C</text>
<text x="116.1" y="44.6">MIN</text>
<text x="126.4" y="44.6">TYP</text>
<text x="138.4" y="44.6">MAX</text>
<text x="149.8" y="44.6">MIN</text>
<text x="161.9" y="44.6">TYP</text>
<text x="175.3" y="44.6">MAX</text>
<text x="185.8" y="42.3">UNIT</text>
<text x="92.4" y="51.3">5.0 V</text>
<text x="102.5" y="49.1">15 pF</text>
<text x="102.5" y="53.6">30 pF</text>
<text x="127.8" y="49.1">2.8</text>
<text x="129.8" y="53.6">3</text>
<text x="140.5" y="49.1">3.2</text>
<text x="140.5" y="53.6">3.5</text>
<text x="165.3" y="49.1">3</text>
<text x="165.3" y="53.6">3</text>
<text x="177.3" y="49.1">3.5</text>
<text x="177.3" y="53.6">4.5</text>
<text x="71.1" y="55.8">DC to 50 MHz</text>
<text x="102.5" y="58.1">15 pF</text>
<text x="129.8" y="58.1">4</text>
<text x="140.5" y="58.1">4.5</text>
<text x="165.3" y="58.1">5</text>
<text x="177.3" y="58.1">5.5</text>
<text x="187.4" y="55.8">ns</text>
<text x="20.8" y="64.8">t</text>
<text x="42.6" y="64.8">Any In</text>
<text x="59.8" y="64.8">Y</text>
<text x="92.4" y="60.3">3.3 V</text>
<text x="102.5" y="62.6">30 pF</text>
<text x="129.8" y="62.6">5</text>
<text x="140.5" y="62.6">5.5</text>
<text x="163.3" y="62.6">5.5</text>
<text x="177.3" y="62.6">6.5</text>
<text x="71.1" y="69.3">DC to 50 MHz</text>
<text x="92.4" y="69.3">2.5 V</text>
<text x="102.5" y="67.1">15 pF</text>
<text x="102.5" y="71.5">30 pF</text>
<text x="127.8" y="67.1">5.5</text>
<text x="127.8" y="71.5">6.5</text>
<text x="140.5" y="67.1">6.5</text>
<text x="142.5" y="71.5">7</text>
<text x="163.3" y="71.5">7.5</text>
<text x="165.3" y="67.1">7</text>
<text x="177.3" y="67.1">7.5</text>
<text x="177.3" y="71.5">8.5</text>
<text x="187.4" y="69.3">ns</text>
<text x="102.5" y="76">15 pF</text>
<text x="128.5" y="76">10</text>
<text x="141.3" y="76">11</text>
<text x="164.2" y="76">11</text>
<text x="178" y="76">12</text>
<text x="71.1" y="78.3">DC to 30 MHz</text>
<text x="92.4" y="78.3">1.8 V</text>
<text x="102.5" y="80.5">30 pF</text>
<text x="128.6" y="80.5">11</text>
<text x="141.1" y="80.5">12</text>
<text x="161.9" y="80.5">12.5</text>
<text x="178" y="80.5">13</text>
<text x="187.4" y="78.3">ns</text>
<text x="92.4" y="87.3">5.0 V</text>
<text x="102.5" y="85">15 pF</text>
<text x="102.5" y="89.5">30 pF</text>
<text x="127.8" y="85">3.5</text>
<text x="127.8" y="89.5">3.8</text>
<text x="140.5" y="89.5">4.2</text>
<text x="142.5" y="85">4</text>
<text x="163.3" y="85">3.5</text>
<text x="165.3" y="89.5">4</text>
<text x="177.3" y="89.5">4.5</text>
<text x="179.4" y="85">4</text>
<text x="71.1" y="91.8">DC to 50 MHz</text>
<text x="102.5" y="94">15 pF</text>
<text x="129.8" y="94">5</text>
<text x="140.5" y="94">5.8</text>
<text x="163.3" y="94">5.8</text>
<text x="177.3" y="94">6.1</text>
<text x="187.4" y="91.8">ns</text>
<text x="20.8" y="100.8">t</text>
<text x="44.3" y="100.8">OE</text>
<text x="59.8" y="100.8">Y</text>
<text x="92.4" y="96.3">3.3 V</text>
<text x="102.5" y="98.5">30 pF</text>
<text x="127.8" y="98.5">5.5</text>
<text x="142.5" y="98.5">6</text>
<text x="163.3" y="98.5">5.7</text>
<text x="177.3" y="98.5">6.5</text>
<text x="71.1" y="105.3">DC to 50 MHz</text>
<text x="92.4" y="105.3">2.5 V</text>
<text x="102.5" y="103">15 pF</text>
<text x="102.5" y="107.5">30 pF</text>
<text x="127.8" y="103">7.5</text>
<text x="129.8" y="107.5">8</text>
<text x="140.5" y="107.5">8.5</text>
<text x="142.5" y="103">8</text>
<text x="163.3" y="103">8.5</text>
<text x="165.3" y="107.5">9</text>
<text x="177.3" y="107.5">9.5</text>
<text x="179.4" y="103">9</text>
<text x="187.4" y="105.3">ns</text>
<text x="102.5" y="112">15 pF</text>
<text x="126.4" y="112">14.5</text>
<text x="141.1" y="112">15</text>
<text x="161.9" y="112">15.5</text>
<text x="175.9" y="112">16.5</text>
<text x="71.1" y="114.3">DC to 30 MHz</text>
<text x="92.4" y="114.3">1.8 V</text>
<text x="102.5" y="116.5">30 pF</text>
<text x="126.4" y="116.5">15.5</text>
<text x="141.1" y="116.5">16</text>
<text x="164" y="116.5">16</text>
<text x="178" y="116.5">17</text>
<text x="187.4" y="114.3">ns</text>
<text x="92.4" y="123.3">5.0 V</text>
<text x="102.5" y="121">15 pF</text>
<text x="102.5" y="125.5">30 pF</text>
<text x="127.8" y="125.5">3.5</text>
<text x="129.8" y="121">3</text>
<text x="140.5" y="121">3.5</text>
<text x="142.5" y="125.5">4</text>
<text x="163.3" y="121">3.5</text>
<text x="165.3" y="125.5">4</text>
<text x="177.3" y="125.5">4.5</text>
<text x="179.4" y="121">4</text>
<text x="71.1" y="127.8">DC to 50 MHz</text>
<text x="102.5" y="130">15 pF</text>
<text x="127.8" y="130">5.3</text>
<text x="140.5" y="130">5.6</text>
<text x="165.3" y="130">6</text>
<text x="177.3" y="130">6.2</text>
<text x="187.4" y="127.8">ns</text>
<text x="20.8" y="136.8">t</text>
<text x="44.3" y="136.8">OE</text>
<text x="59.8" y="136.8">Y</text>
<text x="92.4" y="132.3">3.3 V</text>
<text x="102.5" y="134.5">30 pF</text>
<text x="127.8" y="134.5">5.8</text>
<text x="140.5" y="134.5">6.2</text>
<text x="165.3" y="134.5">7</text>
<text x="177.3" y="134.5">7.5</text>
<text x="71.1" y="141.3">DC to 50 MHz</text>
<text x="92.4" y="141.3">2.5 V</text>
<text x="102.5" y="139">15 pF</text>
<text x="102.5" y="143.5">30 pF</text>
<text x="129.8" y="139">8</text>
<text x="129.8" y="143.5">9</text>
<text x="140.5" y="139">8.5</text>
<text x="140.5" y="143.5">9.5</text>
<text x="161.9" y="143.5">10.5</text>
<text x="165.3" y="139">9</text>
<text x="177.3" y="139">9.5</text>
<text x="178.2" y="143.5">11</text>
<text x="187.4" y="141.3">ns</text>
<text x="102.5" y="148">15 pF</text>
<text x="128.5" y="148">17</text>
<text x="139.1" y="148">17.5</text>
<text x="164" y="148">18</text>
<text x="175.9" y="148">18.5</text>
<text x="71.1" y="150.3">DC to 30 MHz</text>
<text x="92.4" y="150.3">1.8 V</text>
<text x="102.5" y="152.5">30 pF</text>
<text x="128.5" y="152.5">18</text>
<text x="139.1" y="152.5">18.5</text>
<text x="164" y="152.5">19</text>
<text x="178" y="152.5">20</text>
<text x="187.4" y="150.3">ns</text>
<text x="92.4" y="159.3">5.0 V</text>
<text x="102.5" y="157">15 pF</text>
<text x="102.5" y="161.5">30 pF</text>
<text x="127.8" y="161.5">3.5</text>
<text x="129.8" y="157">3</text>
<text x="140.5" y="157">3.5</text>
<text x="142.5" y="161.5">4</text>
<text x="163.3" y="157">3.5</text>
<text x="165.3" y="161.5">4</text>
<text x="177.3" y="161.5">4.5</text>
<text x="179.4" y="157">4</text>
<text x="71.1" y="163.8">DC to 50 MHz</text>
<text x="102.5" y="166">15 pF</text>
<text x="127.8" y="166">3.5</text>
<text x="142.5" y="166">4</text>
<text x="163.3" y="166">4.5</text>
<text x="179.4" y="166">5</text>
<text x="187.4" y="163.8">ns</text>
<text x="20.8" y="172.8">t</text>
<text x="44.3" y="172.8">OE</text>
<text x="59.8" y="172.8">Y</text>
<text x="92.4" y="168.3">3.3 V</text>
<text x="102.5" y="170.5">30 pF</text>
<text x="129.8" y="170.5">5</text>
<text x="142.5" y="170.5">6</text>
<text x="163.3" y="170.5">6.5</text>
<text x="179.4" y="170.5">7</text>
<text x="71.1" y="177.3">DC to 50 MHz</text>
<text x="92.4" y="177.3">2.5 V</text>
<text x="102.5" y="175">15 pF</text>
<text x="102.5" y="179.5">30 pF</text>
<text x="127.8" y="175">5.5</text>
<text x="127.8" y="179.5">7.5</text>
<text x="142.5" y="175">6</text>
<text x="142.5" y="179.5">8</text>
<text x="165.3" y="175">6</text>
<text x="165.3" y="179.5">8</text>
<text x="177.3" y="175">6.5</text>
<text x="179.4" y="179.5">9</text>
<text x="187.4" y="177.3">ns</text>
<text x="102.5" y="184">15 pF</text>
<text x="127.8" y="184">7.5</text>
<text x="142.5" y="184">8</text>
<text x="165.3" y="184">8</text>
<text x="177.3" y="184">8.5</text>
<text x="71.1" y="186.2">DC to 30 MHz</text>
<text x="92.4" y="186.2">1.8 V</text>
<text x="102.5" y="188.5">30 pF</text>
<text x="128.6" y="188.5">11</text>
<text x="141.1" y="188.5">12</text>
<text x="164" y="188.5">12</text>
<text x="178" y="188.5">13</text>
<text x="187.4" y="186.2">ns</text>
<text x="92.4" y="195.2">5.0 V</text>
<text x="102.5" y="193">15 pF</text>
<text x="102.5" y="197.5">30 pF</text>
<text x="129.8" y="193">2</text>
<text x="129.8" y="197.5">2</text>
<text x="140.5" y="193">2.5</text>
<text x="142.5" y="197.5">3</text>
<text x="165.3" y="193">2</text>
<text x="165.3" y="197.5">2</text>
<text x="177.3" y="193">2.7</text>
<text x="177.3" y="197.5">3.2</text>
<text x="71.1" y="199.7">DC to 50 MHz</text>
<text x="102.5" y="202">15 pF</text>
<text x="127.8" y="202">2.3</text>
<text x="140.5" y="202">2.8</text>
<text x="163.3" y="202">2.5</text>
<text x="177.3" y="202">3.2</text>
<text x="187.4" y="199.7">ns</text>
<text x="20.8" y="208.7">t</text>
<text x="44.3" y="208.7">OE</text>
<text x="59.8" y="208.7">Y</text>
<text x="92.4" y="204.2">3.3 V</text>
<text x="102.5" y="206.5">30 pF</text>
<text x="127.8" y="206.5">2.8</text>
<text x="140.5" y="206.5">3.2</text>
<text x="163.3" y="206.5">3.3</text>
<text x="179.4" y="206.5">4</text>
<text x="71.1" y="213.2">DC to 50 MHz</text>
<text x="92.4" y="213.2">2.5 V</text>
<text x="102.5" y="211">15 pF</text>
<text x="102.5" y="215.5">30 pF</text>
<text x="127.8" y="211">3.3</text>
<text x="129.8" y="215.5">4</text>
<text x="140.5" y="211">3.8</text>
<text x="140.5" y="215.5">4.3</text>
<text x="163.3" y="211">3.8</text>
<text x="163.3" y="215.5">4.2</text>
<text x="177.3" y="211">4.2</text>
<text x="179.4" y="215.5">5</text>
<text x="187.4" y="213.2">ns</text>
<text x="102.5" y="220">15 pF</text>
<text x="129.8" y="220">5</text>
<text x="140.5" y="220">5.5</text>
<text x="165.3" y="220">5</text>
<text x="177.3" y="220">5.7</text>
<text x="71.1" y="222.2">DC to 30 MHz</text>
<text x="92.4" y="222.2">1.8 V</text>
<text x="102.5" y="224.5">30 pF</text>
<text x="127.8" y="224.5">6.5</text>
<text x="142.5" y="224.5">7</text>
<text x="165.3" y="224.5">7</text>
<text x="177.3" y="224.5">8.5</text>
<text x="187.4" y="222.2">ns</text>
<text x="71.1" y="231.9">DC to 50 MHz</text>
<text x="92.4" y="229">5.0 V</text>
<text x="94.2" y="231.9">to</text>
<text x="102.5" y="231.9">15 pF</text>
<text x="20.8" y="234.2">t</text>
<text x="42.6" y="234.2">Any In</text>
<text x="59.8" y="234.2">Y</text>
<text x="71.1" y="239.4">DC to 30 MHz</text>
<text x="92.4" y="234.9">2.5 V</text>
<text x="92.4" y="239.4">1.8 V</text>
<text x="102.5" y="239.4">15 pF</text>
<text x="152.9" y="234.2">1</text>
<text x="179.4" y="234.2">1</text>
<text x="187.4" y="234.2">ns</text>
<text x="19" y="265.9">Copyright © 2022 Texas Instruments Incorporated</text>
</g>
<g font-size="1.9">
<text x="123.6" y="40.6">A</text>
<text x="153" y="40.6">A</text>
<text x="94.8" y="42.8">CC</text>
<text x="105.9" y="42.8">L</text>
<text x="21.5" y="65.3">pd</text>
<text x="21.5" y="101.3">PZH</text>
<text x="21.5" y="137.3">PZL</text>
<text x="21.5" y="173.2">PHZ</text>
<text x="21.5" y="209.2">PLZ</text>
<text x="21.5" y="234.7">sk</text>
</g>
</g></defs>
<g fill="#d8d8d8">
<path d="M20 37.1h175.9v4.5h-175.9z" fill-rule="evenodd"/>
<path d="M20.1 37.2h18.4v8.8h-18.4z" fill-rule="evenodd"/>
<path d="M38.6 37.2h15v8.8h-15z" fill-rule="evenodd"/>
<path d="M53.7 37.2h13.8v8.8h-13.8z" fill-rule="evenodd"/>
<path d="M67.6 37.2h22.4v8.8h-22.4z" fill-rule="evenodd"/>
<path d="M90.2 37.2h10.2v8.8h-10.2z" fill-rule="evenodd"/>
<path d="M100.5 37.2h10.2v8.8h-10.2z" fill-rule="evenodd"/>
<path d="M110.9 37.2h33.7v4.3h-33.7z" fill-rule="evenodd"/>
<path d="M144.7 37.2h36.7v4.3h-36.7z" fill-rule="evenodd"/>
<path d="M181.6 37.2h14.2v8.8h-14.2z" fill-rule="evenodd"/>
<path d="M110.9 41.7h10.5v4.3h-10.5z" fill-rule="evenodd"/>
<path d="M121.4 41.7h10.5v4.3h-10.5z" fill-rule="evenodd"/>
<path d="M131.9 41.7h12.7v4.3h-12.7z" fill-rule="evenodd"/>
<path d="M144.7 41.7h10.3v4.3h-10.3z" fill-rule="evenodd"/>
<path d="M155 41.7h12.4v4.3h-12.4z" fill-rule="evenodd"/>
<path d="M167.4 41.7h14v4.3h-14z" fill-rule="evenodd"/>
</g>
<g fill="none" stroke="#000" stroke-width=".2">
<path d="M19.9 37.1h176.1M20 37v204M38.5 37v204M53.6 37v204M67.5 37v204M90.1 37v204M100.4 37v204M110.8 37v204M144.7 37v204M181.5 37v204M195.9 37v204M19.9 46.1h176.1"/>
<path d="M90.1 55.1h91.5M100.4 50.6h81.2M100.4 59.6h81.2M110.8 41.6h70.8M67.5 64.1h128.5M67.5 73.1h128.5M100.4 68.6h81.2M100.4 77.6h81.2M19.9 82.1h176.1M44.3 98.8h3.6M90.1 91.1h91.5M100.4 86.6h81.2"/>
<path d="M100.4 95.6h81.2M19.9 118.1h176.1M67.5 100.1h128.5M67.5 109.1h128.5M100.4 104.6h81.2M100.4 113.6h81.2M44.3 134.8h3.6M67.5 136.1h128.5M100.4 122.6h81.2M100.4 131.6h81.2M181.6 127.1h-91.5M19.9 154h176.1"/>
<path d="M67.5 145.1h128.5M100.4 140.6h81.2M100.4 149.6h81.2M100.4 158.5h81.2M44.3 170.7h3.6M67.5 172h128.5M90.1 163h91.5M100.4 167.5h81.2M100.4 176.5h81.2M19.9 190h176.1M67.5 181h128.5M100.4 185.5h81.2"/>
<path d="M100.4 194.5h81.2M181.6 199h-91.5M44.3 206.7h3.6M67.5 208h128.5M67.5 217h128.5M100.4 203.5h81.2M100.4 212.5h81.2M67.5 236.4h43.4M100.4 221.5h81.2M196 226h-176.1M19.9 240.9h176.1"/>
</g>
<path d="M27.7 11.6l-.2 .6 .5-.2h.6v.1v2.2l-.2 .4h1l-.2-.4v-2.2v-.1h.5l.5 .2-.1-.6zM29.8 12.4l.2 .3v1.6l-.2 .4h1.9l.1-.6a1.08 1.08 0 0 1-1.3 .2v-.7h.6l.4 .2v-.7l-.4 .2h-.6v-.5l.2-.2a1 1 0 0 1 1 .3l-.1-.5zM31.8 12.4l1 1.1-1 1.2h.9l-.2-.2 .4-.8 .5 .8-.2 .2h1.6l-.2-.2 .1-.5h1l.1 .5-.1 .2h.9l-.2-.4-.8-1.9h-.5l-1 2.1-.8-1.1 .9-1h-.8l.2 .2-.5 .6-.3-.6 .1-.2zM35.2 12.8l.4 1h-.8zM36.8 12.5a.65 .65 0 0 0-.2 .7 .65 .65 0 0 0 .6 .5l.7 .1 .1 .3a.79 .79 0 0 1-.7 .4 .79 .79 0 0 1-.7-.5l.1 .7 .2-.1a.93 .93 0 0 0 1.1 0 .93 .93 0 0 0 .4-.9 1.46 1.46 0 0 0-1.2-.6l-.1-.3a1.09 1.09 0 0 1 1.2 .2l-.2-.6-.1 .1-.6-.2zM28.4 15.2l.2 .4v2.2l-.2 .4h1l-.2-.4v-2.2l.2-.4zM29.6 15.9l.2 .4v1.5l-.2 .4h.8l-.3-.4v-1.3l1.7 1.8v-2l.2-.4h-.8l.2 .2 .1 1.1-1.2-1.3zM32.3 16a.65 .65 0 0 0-.2 .8 .65 .65 0 0 0 .7 .4l.6 .2 .1 .2a.79 .79 0 0 1-.7 .4 .79 .79 0 0 1-.7-.5l.1 .7 .2-.1a.93 .93 0 0 0 1.1 .1 .93 .93 0 0 0 .4-1 1.46 1.46 0 0 0-1.2-.5l-.1-.4a1.09 1.09 0 0 1 1.2 .2l-.2-.6-.1 .1-.6-.1zM34.1 15.9l-.1 .6a.63 .63 0 0 1 .7-.3l.1 1.6-.3 .4h1l-.2-.4v-1.6a.66 .66 0 0 1 .8 .3l-.1-.6zM36.2 15.9l.2 .4v1.5l-.2 .4h.9l-.2-.2v-.7h.5l.1 .2a.79 .79 0 0 0 1.2 .6l-1-.9a.61 .61 0 0 0 .6-.6 .61 .61 0 0 0-.5-.7zM36.9 16.2h.2a.47 .47 0 0 1 .5 .1 .47 .47 0 0 1 .1 .5l-.2 .1-.6 .1zM38.5 15.9l.2 .2a2.27 2.27 0 0 0 .4 2 1.04 1.04 0 0 0 1.7-.7v-1.3l.2-.2h-.8l.2 .4v1.1a.6 .6 0 0 1-.6 .6 .6 .6 0 0 1-.6-.6v-1.1l.3-.4zM41.1 15.9l.2 .4v1.5l-.2 .4h.7l-.2-.4v-1.4l.9 1.9 .8-1.9v1.4l-.2 .4h1l-.3-.4v-1.5l.3-.4h-.8l-.7 1.5-.7-1.5zM44.3 15.9l.2 .4v1.5l-.2 .4h1.9l.1-.6a1.09 1.09 0 0 1-1.3 .2v-.7h.6l.4 .2v-.6l-.4 .2h-.6v-.6l.2-.1a1.01 1.01 0 0 1 1 .3l-.1-.6zM46.4 15.9l.3 .4v1.5l-.3 .4h.8l-.2-.4v-1.3l1.6 1.8v-2l.2-.4h-.7l.2 .2v1.1l-1.2-1.3zM49 15.9l-.1 .6a.63 .63 0 0 1 .8-.3v1.6l-.3 .4h1l-.2-.4v-1.6a.66 .66 0 0 1 .8 .3l-.1-.6zM51.4 16a.65 .65 0 0 0-.2 .8 .65 .65 0 0 0 .6 .4l.6 .2 .2 .2a.79 .79 0 0 1-.8 .4 .79 .79 0 0 1-.6-.5l.1 .7 .2-.1a.93 .93 0 0 0 1 .1 .93 .93 0 0 0 .5-1 1.46 1.46 0 0 0-1.3-.5l-.1-.4a1.09 1.09 0 0 1 1.3 .2l-.2-.6-.2 .1-.5-.1z" fill="#231f20"/>
<path d="M21.1 10.3v2.7h-2.1l.1 .4 .9 1a.95 .95 0 0 0 .9 .9 .59 .59 0 0 1 .6-.4 .59 .59 0 0 1 .5 .3l.4 .8a1.59 1.59 0 0 0 2.1 1.4 1.61 1.61 0 0 1 1-2.3l1-.3-.1-1.5a1.59 1.59 0 0 1-.4-1.7h-1.4l-.2 .9h.5l-.1 .9h-.5l-.2 .9v.3l.4 .1-.2 .9h-.6a.73 .73 0 0 1-1.1-.7l.3-1.5h-.5l.2-.9h.5l.2-.9h-.5v-1.3zM23.6 11.6l-.6 3.1h.7l.6-3.1zM23.8 10.7l-.1 .6h.7l.1-.6z" fill="#ed1c24"/>
<path d="M19 22.9h177.8M19.1 262.3h179.9" fill="none" stroke="#000" stroke-width=".53"/>
<use href="#words"/>
</svg>
